VERSION 5.7 ;
  NOWIREEXTENSIONATPIN ON ;
  DIVIDERCHAR "/" ;
  BUSBITCHARS "[]" ;
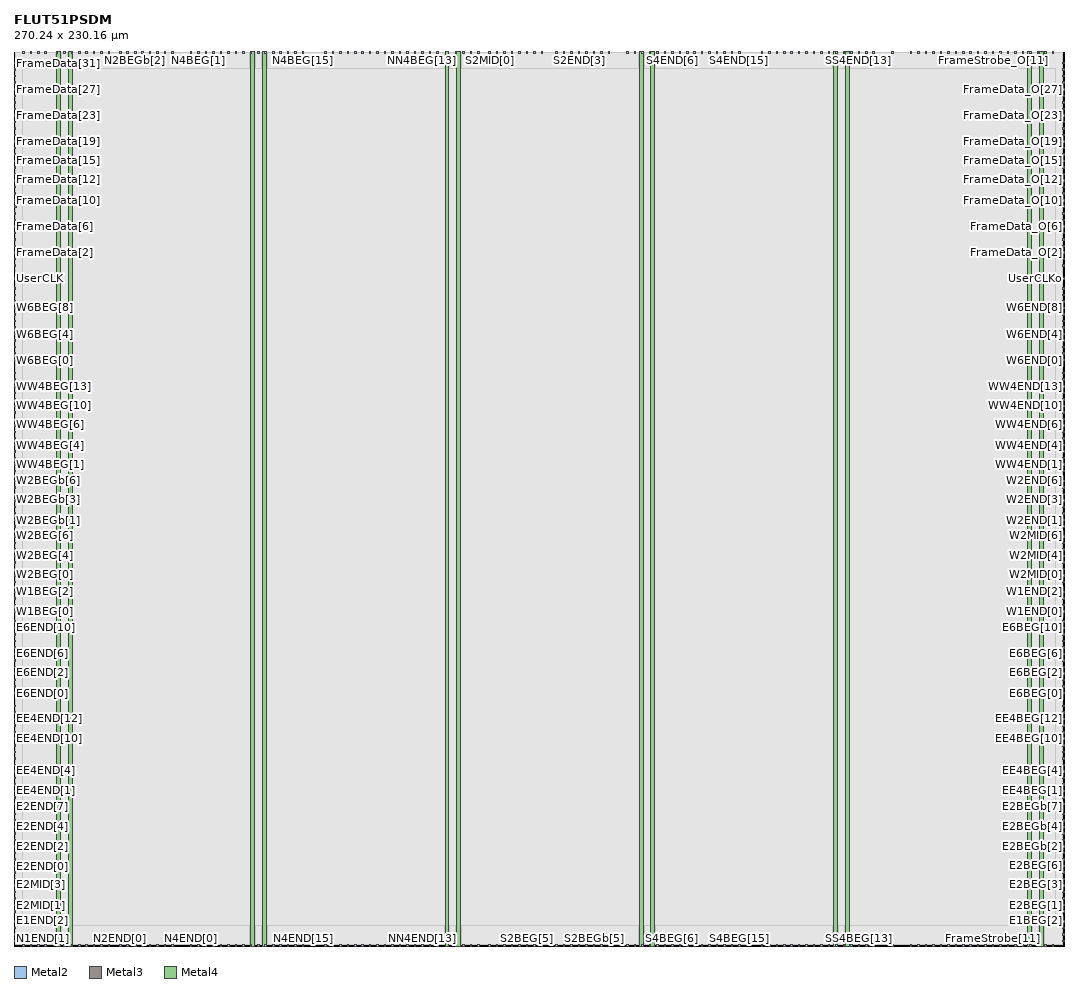
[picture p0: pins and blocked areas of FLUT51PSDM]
MACRO FLUT51PSDM
  CLASS BLOCK ;
  FOREIGN FLUT51PSDM ;
  ORIGIN 0.000 0.000 ;
  SIZE 270.240 BY 230.160 ;
  PIN Ci
    DIRECTION INPUT ;
    USE SIGNAL ;
    ANTENNAGATEAREA 0.241800 ;
    PORT
      LAYER Metal2 ;
        RECT 225.880 0.000 226.280 0.400 ;
    END
  END Ci
  PIN Co
    DIRECTION OUTPUT ;
    USE SIGNAL ;
    ANTENNADIFFAREA 2.647800 ;
    PORT
      LAYER Metal2 ;
        RECT 225.880 229.760 226.280 230.160 ;
    END
  END Co
  PIN E1BEG[0]
    DIRECTION OUTPUT ;
    USE SIGNAL ;
    ANTENNADIFFAREA 2.724000 ;
    PORT
      LAYER Metal3 ;
        RECT 269.840 1.060 270.240 1.460 ;
    END
  END E1BEG[0]
  PIN E1BEG[1]
    DIRECTION OUTPUT ;
    USE SIGNAL ;
    ANTENNADIFFAREA 2.724000 ;
    PORT
      LAYER Metal3 ;
        RECT 269.840 2.740 270.240 3.140 ;
    END
  END E1BEG[1]
  PIN E1BEG[2]
    DIRECTION OUTPUT ;
    USE SIGNAL ;
    ANTENNADIFFAREA 2.724000 ;
    PORT
      LAYER Metal3 ;
        RECT 269.840 4.420 270.240 4.820 ;
    END
  END E1BEG[2]
  PIN E1BEG[3]
    DIRECTION OUTPUT ;
    USE SIGNAL ;
    ANTENNADIFFAREA 2.724000 ;
    PORT
      LAYER Metal3 ;
        RECT 269.840 6.100 270.240 6.500 ;
    END
  END E1BEG[3]
  PIN E1END[0]
    DIRECTION INPUT ;
    USE SIGNAL ;
    ANTENNAGATEAREA 1.705600 ;
    PORT
      LAYER Metal3 ;
        RECT 0.000 1.060 0.400 1.460 ;
    END
  END E1END[0]
  PIN E1END[1]
    DIRECTION INPUT ;
    USE SIGNAL ;
    ANTENNAGATEAREA 2.132000 ;
    PORT
      LAYER Metal3 ;
        RECT 0.000 2.740 0.400 3.140 ;
    END
  END E1END[1]
  PIN E1END[2]
    DIRECTION INPUT ;
    USE SIGNAL ;
    ANTENNAGATEAREA 1.492400 ;
    ANTENNADIFFAREA 42.323399 ;
    PORT
      LAYER Metal3 ;
        RECT 0.000 4.420 0.400 4.820 ;
    END
  END E1END[2]
  PIN E1END[3]
    DIRECTION INPUT ;
    USE SIGNAL ;
    ANTENNAGATEAREA 2.145000 ;
    PORT
      LAYER Metal3 ;
        RECT 0.000 6.100 0.400 6.500 ;
    END
  END E1END[3]
  PIN E2BEG[0]
    DIRECTION OUTPUT ;
    USE SIGNAL ;
    ANTENNADIFFAREA 2.724000 ;
    PORT
      LAYER Metal3 ;
        RECT 269.840 8.620 270.240 9.020 ;
    END
  END E2BEG[0]
  PIN E2BEG[1]
    DIRECTION OUTPUT ;
    USE SIGNAL ;
    ANTENNADIFFAREA 2.724000 ;
    PORT
      LAYER Metal3 ;
        RECT 269.840 10.300 270.240 10.700 ;
    END
  END E2BEG[1]
  PIN E2BEG[2]
    DIRECTION OUTPUT ;
    USE SIGNAL ;
    ANTENNADIFFAREA 2.724000 ;
    PORT
      LAYER Metal3 ;
        RECT 269.840 11.980 270.240 12.380 ;
    END
  END E2BEG[2]
  PIN E2BEG[3]
    DIRECTION OUTPUT ;
    USE SIGNAL ;
    ANTENNADIFFAREA 2.724000 ;
    PORT
      LAYER Metal3 ;
        RECT 269.840 13.660 270.240 14.060 ;
    END
  END E2BEG[3]
  PIN E2BEG[4]
    DIRECTION OUTPUT ;
    USE SIGNAL ;
    ANTENNADIFFAREA 2.724000 ;
    PORT
      LAYER Metal3 ;
        RECT 269.840 15.340 270.240 15.740 ;
    END
  END E2BEG[4]
  PIN E2BEG[5]
    DIRECTION OUTPUT ;
    USE SIGNAL ;
    ANTENNADIFFAREA 2.724000 ;
    PORT
      LAYER Metal3 ;
        RECT 269.840 17.020 270.240 17.420 ;
    END
  END E2BEG[5]
  PIN E2BEG[6]
    DIRECTION OUTPUT ;
    USE SIGNAL ;
    ANTENNADIFFAREA 2.724000 ;
    PORT
      LAYER Metal3 ;
        RECT 269.840 18.700 270.240 19.100 ;
    END
  END E2BEG[6]
  PIN E2BEG[7]
    DIRECTION OUTPUT ;
    USE SIGNAL ;
    ANTENNADIFFAREA 2.724000 ;
    PORT
      LAYER Metal3 ;
        RECT 269.840 20.380 270.240 20.780 ;
    END
  END E2BEG[7]
  PIN E2BEGb[0]
    DIRECTION OUTPUT ;
    USE SIGNAL ;
    ANTENNADIFFAREA 2.724000 ;
    PORT
      LAYER Metal3 ;
        RECT 269.840 22.060 270.240 22.460 ;
    END
  END E2BEGb[0]
  PIN E2BEGb[1]
    DIRECTION OUTPUT ;
    USE SIGNAL ;
    ANTENNADIFFAREA 2.724000 ;
    PORT
      LAYER Metal3 ;
        RECT 269.840 23.740 270.240 24.140 ;
    END
  END E2BEGb[1]
  PIN E2BEGb[2]
    DIRECTION OUTPUT ;
    USE SIGNAL ;
    ANTENNADIFFAREA 2.724000 ;
    PORT
      LAYER Metal3 ;
        RECT 269.840 25.420 270.240 25.820 ;
    END
  END E2BEGb[2]
  PIN E2BEGb[3]
    DIRECTION OUTPUT ;
    USE SIGNAL ;
    ANTENNADIFFAREA 2.724000 ;
    PORT
      LAYER Metal3 ;
        RECT 269.840 27.100 270.240 27.500 ;
    END
  END E2BEGb[3]
  PIN E2BEGb[4]
    DIRECTION OUTPUT ;
    USE SIGNAL ;
    ANTENNADIFFAREA 2.724000 ;
    PORT
      LAYER Metal3 ;
        RECT 269.840 28.780 270.240 29.180 ;
    END
  END E2BEGb[4]
  PIN E2BEGb[5]
    DIRECTION OUTPUT ;
    USE SIGNAL ;
    ANTENNADIFFAREA 2.724000 ;
    PORT
      LAYER Metal3 ;
        RECT 269.840 30.460 270.240 30.860 ;
    END
  END E2BEGb[5]
  PIN E2BEGb[6]
    DIRECTION OUTPUT ;
    USE SIGNAL ;
    ANTENNADIFFAREA 2.724000 ;
    PORT
      LAYER Metal3 ;
        RECT 269.840 32.140 270.240 32.540 ;
    END
  END E2BEGb[6]
  PIN E2BEGb[7]
    DIRECTION OUTPUT ;
    USE SIGNAL ;
    ANTENNADIFFAREA 2.724000 ;
    PORT
      LAYER Metal3 ;
        RECT 269.840 33.820 270.240 34.220 ;
    END
  END E2BEGb[7]
  PIN E2END[0]
    DIRECTION INPUT ;
    USE SIGNAL ;
    ANTENNAGATEAREA 0.852800 ;
    ANTENNADIFFAREA 8.061600 ;
    PORT
      LAYER Metal3 ;
        RECT 0.000 22.060 0.400 22.460 ;
    END
  END E2END[0]
  PIN E2END[1]
    DIRECTION INPUT ;
    USE SIGNAL ;
    ANTENNAGATEAREA 1.279200 ;
    PORT
      LAYER Metal3 ;
        RECT 0.000 23.740 0.400 24.140 ;
    END
  END E2END[1]
  PIN E2END[2]
    DIRECTION INPUT ;
    USE SIGNAL ;
    ANTENNAGATEAREA 1.279200 ;
    PORT
      LAYER Metal3 ;
        RECT 0.000 25.420 0.400 25.820 ;
    END
  END E2END[2]
  PIN E2END[3]
    DIRECTION INPUT ;
    USE SIGNAL ;
    ANTENNAGATEAREA 1.492400 ;
    PORT
      LAYER Metal3 ;
        RECT 0.000 27.100 0.400 27.500 ;
    END
  END E2END[3]
  PIN E2END[4]
    DIRECTION INPUT ;
    USE SIGNAL ;
    ANTENNAGATEAREA 1.705600 ;
    PORT
      LAYER Metal3 ;
        RECT 0.000 28.780 0.400 29.180 ;
    END
  END E2END[4]
  PIN E2END[5]
    DIRECTION INPUT ;
    USE SIGNAL ;
    ANTENNAGATEAREA 1.492400 ;
    PORT
      LAYER Metal3 ;
        RECT 0.000 30.460 0.400 30.860 ;
    END
  END E2END[5]
  PIN E2END[6]
    DIRECTION INPUT ;
    USE SIGNAL ;
    ANTENNAGATEAREA 1.492400 ;
    PORT
      LAYER Metal3 ;
        RECT 0.000 32.140 0.400 32.540 ;
    END
  END E2END[6]
  PIN E2END[7]
    DIRECTION INPUT ;
    USE SIGNAL ;
    ANTENNAGATEAREA 1.066000 ;
    PORT
      LAYER Metal3 ;
        RECT 0.000 33.820 0.400 34.220 ;
    END
  END E2END[7]
  PIN E2MID[0]
    DIRECTION INPUT ;
    USE SIGNAL ;
    ANTENNAGATEAREA 2.099500 ;
    PORT
      LAYER Metal3 ;
        RECT 0.000 8.620 0.400 9.020 ;
    END
  END E2MID[0]
  PIN E2MID[1]
    DIRECTION INPUT ;
    USE SIGNAL ;
    ANTENNAGATEAREA 1.459900 ;
    PORT
      LAYER Metal3 ;
        RECT 0.000 10.300 0.400 10.700 ;
    END
  END E2MID[1]
  PIN E2MID[2]
    DIRECTION INPUT ;
    USE SIGNAL ;
    ANTENNAGATEAREA 1.673100 ;
    PORT
      LAYER Metal3 ;
        RECT 0.000 11.980 0.400 12.380 ;
    END
  END E2MID[2]
  PIN E2MID[3]
    DIRECTION INPUT ;
    USE SIGNAL ;
    ANTENNAGATEAREA 2.312700 ;
    PORT
      LAYER Metal3 ;
        RECT 0.000 13.660 0.400 14.060 ;
    END
  END E2MID[3]
  PIN E2MID[4]
    DIRECTION INPUT ;
    USE SIGNAL ;
    ANTENNAGATEAREA 1.673100 ;
    PORT
      LAYER Metal3 ;
        RECT 0.000 15.340 0.400 15.740 ;
    END
  END E2MID[4]
  PIN E2MID[5]
    DIRECTION INPUT ;
    USE SIGNAL ;
    ANTENNAGATEAREA 1.459900 ;
    PORT
      LAYER Metal3 ;
        RECT 0.000 17.020 0.400 17.420 ;
    END
  END E2MID[5]
  PIN E2MID[6]
    DIRECTION INPUT ;
    USE SIGNAL ;
    ANTENNAGATEAREA 1.699100 ;
    PORT
      LAYER Metal3 ;
        RECT 0.000 18.700 0.400 19.100 ;
    END
  END E2MID[6]
  PIN E2MID[7]
    DIRECTION INPUT ;
    USE SIGNAL ;
    ANTENNAGATEAREA 1.459900 ;
    PORT
      LAYER Metal3 ;
        RECT 0.000 20.380 0.400 20.780 ;
    END
  END E2MID[7]
  PIN E6BEG[0]
    DIRECTION OUTPUT ;
    USE SIGNAL ;
    ANTENNADIFFAREA 2.724000 ;
    PORT
      LAYER Metal3 ;
        RECT 269.840 64.900 270.240 65.300 ;
    END
  END E6BEG[0]
  PIN E6BEG[10]
    DIRECTION OUTPUT ;
    USE SIGNAL ;
    ANTENNADIFFAREA 2.724000 ;
    PORT
      LAYER Metal3 ;
        RECT 269.840 81.700 270.240 82.100 ;
    END
  END E6BEG[10]
  PIN E6BEG[11]
    DIRECTION OUTPUT ;
    USE SIGNAL ;
    ANTENNADIFFAREA 2.724000 ;
    PORT
      LAYER Metal3 ;
        RECT 269.840 83.380 270.240 83.780 ;
    END
  END E6BEG[11]
  PIN E6BEG[1]
    DIRECTION OUTPUT ;
    USE SIGNAL ;
    ANTENNADIFFAREA 2.724000 ;
    PORT
      LAYER Metal3 ;
        RECT 269.840 66.580 270.240 66.980 ;
    END
  END E6BEG[1]
  PIN E6BEG[2]
    DIRECTION OUTPUT ;
    USE SIGNAL ;
    ANTENNADIFFAREA 2.724000 ;
    PORT
      LAYER Metal3 ;
        RECT 269.840 68.260 270.240 68.660 ;
    END
  END E6BEG[2]
  PIN E6BEG[3]
    DIRECTION OUTPUT ;
    USE SIGNAL ;
    ANTENNADIFFAREA 2.724000 ;
    PORT
      LAYER Metal3 ;
        RECT 269.840 69.940 270.240 70.340 ;
    END
  END E6BEG[3]
  PIN E6BEG[4]
    DIRECTION OUTPUT ;
    USE SIGNAL ;
    ANTENNADIFFAREA 2.724000 ;
    PORT
      LAYER Metal3 ;
        RECT 269.840 71.620 270.240 72.020 ;
    END
  END E6BEG[4]
  PIN E6BEG[5]
    DIRECTION OUTPUT ;
    USE SIGNAL ;
    ANTENNADIFFAREA 2.724000 ;
    PORT
      LAYER Metal3 ;
        RECT 269.840 73.300 270.240 73.700 ;
    END
  END E6BEG[5]
  PIN E6BEG[6]
    DIRECTION OUTPUT ;
    USE SIGNAL ;
    ANTENNADIFFAREA 2.724000 ;
    PORT
      LAYER Metal3 ;
        RECT 269.840 74.980 270.240 75.380 ;
    END
  END E6BEG[6]
  PIN E6BEG[7]
    DIRECTION OUTPUT ;
    USE SIGNAL ;
    ANTENNADIFFAREA 2.724000 ;
    PORT
      LAYER Metal3 ;
        RECT 269.840 76.660 270.240 77.060 ;
    END
  END E6BEG[7]
  PIN E6BEG[8]
    DIRECTION OUTPUT ;
    USE SIGNAL ;
    ANTENNADIFFAREA 2.724000 ;
    PORT
      LAYER Metal3 ;
        RECT 269.840 78.340 270.240 78.740 ;
    END
  END E6BEG[8]
  PIN E6BEG[9]
    DIRECTION OUTPUT ;
    USE SIGNAL ;
    ANTENNADIFFAREA 2.724000 ;
    PORT
      LAYER Metal3 ;
        RECT 269.840 80.020 270.240 80.420 ;
    END
  END E6BEG[9]
  PIN E6END[0]
    DIRECTION INPUT ;
    USE SIGNAL ;
    ANTENNAGATEAREA 1.918800 ;
    PORT
      LAYER Metal3 ;
        RECT 0.000 64.900 0.400 65.300 ;
    END
  END E6END[0]
  PIN E6END[10]
    DIRECTION INPUT ;
    USE SIGNAL ;
    ANTENNAGATEAREA 0.180700 ;
    PORT
      LAYER Metal3 ;
        RECT 0.000 81.700 0.400 82.100 ;
    END
  END E6END[10]
  PIN E6END[11]
    DIRECTION INPUT ;
    USE SIGNAL ;
    ANTENNAGATEAREA 0.180700 ;
    PORT
      LAYER Metal3 ;
        RECT 0.000 83.380 0.400 83.780 ;
    END
  END E6END[11]
  PIN E6END[1]
    DIRECTION INPUT ;
    USE SIGNAL ;
    ANTENNAGATEAREA 2.345200 ;
    PORT
      LAYER Metal3 ;
        RECT 0.000 66.580 0.400 66.980 ;
    END
  END E6END[1]
  PIN E6END[2]
    DIRECTION INPUT ;
    USE SIGNAL ;
    ANTENNAGATEAREA 0.180700 ;
    PORT
      LAYER Metal3 ;
        RECT 0.000 68.260 0.400 68.660 ;
    END
  END E6END[2]
  PIN E6END[3]
    DIRECTION INPUT ;
    USE SIGNAL ;
    ANTENNAGATEAREA 0.180700 ;
    PORT
      LAYER Metal3 ;
        RECT 0.000 69.940 0.400 70.340 ;
    END
  END E6END[3]
  PIN E6END[4]
    DIRECTION INPUT ;
    USE SIGNAL ;
    ANTENNAGATEAREA 0.180700 ;
    PORT
      LAYER Metal3 ;
        RECT 0.000 71.620 0.400 72.020 ;
    END
  END E6END[4]
  PIN E6END[5]
    DIRECTION INPUT ;
    USE SIGNAL ;
    ANTENNAGATEAREA 0.180700 ;
    PORT
      LAYER Metal3 ;
        RECT 0.000 73.300 0.400 73.700 ;
    END
  END E6END[5]
  PIN E6END[6]
    DIRECTION INPUT ;
    USE SIGNAL ;
    ANTENNAGATEAREA 0.180700 ;
    PORT
      LAYER Metal3 ;
        RECT 0.000 74.980 0.400 75.380 ;
    END
  END E6END[6]
  PIN E6END[7]
    DIRECTION INPUT ;
    USE SIGNAL ;
    ANTENNAGATEAREA 0.180700 ;
    PORT
      LAYER Metal3 ;
        RECT 0.000 76.660 0.400 77.060 ;
    END
  END E6END[7]
  PIN E6END[8]
    DIRECTION INPUT ;
    USE SIGNAL ;
    ANTENNAGATEAREA 0.180700 ;
    PORT
      LAYER Metal3 ;
        RECT 0.000 78.340 0.400 78.740 ;
    END
  END E6END[8]
  PIN E6END[9]
    DIRECTION INPUT ;
    USE SIGNAL ;
    ANTENNAGATEAREA 0.180700 ;
    PORT
      LAYER Metal3 ;
        RECT 0.000 80.020 0.400 80.420 ;
    END
  END E6END[9]
  PIN EE4BEG[0]
    DIRECTION OUTPUT ;
    USE SIGNAL ;
    ANTENNADIFFAREA 2.724000 ;
    PORT
      LAYER Metal3 ;
        RECT 269.840 36.340 270.240 36.740 ;
    END
  END EE4BEG[0]
  PIN EE4BEG[10]
    DIRECTION OUTPUT ;
    USE SIGNAL ;
    ANTENNADIFFAREA 2.724000 ;
    PORT
      LAYER Metal3 ;
        RECT 269.840 53.140 270.240 53.540 ;
    END
  END EE4BEG[10]
  PIN EE4BEG[11]
    DIRECTION OUTPUT ;
    USE SIGNAL ;
    ANTENNADIFFAREA 2.724000 ;
    PORT
      LAYER Metal3 ;
        RECT 269.840 54.820 270.240 55.220 ;
    END
  END EE4BEG[11]
  PIN EE4BEG[12]
    DIRECTION OUTPUT ;
    USE SIGNAL ;
    ANTENNADIFFAREA 2.724000 ;
    PORT
      LAYER Metal3 ;
        RECT 269.840 56.500 270.240 56.900 ;
    END
  END EE4BEG[12]
  PIN EE4BEG[13]
    DIRECTION OUTPUT ;
    USE SIGNAL ;
    ANTENNADIFFAREA 2.724000 ;
    PORT
      LAYER Metal3 ;
        RECT 269.840 58.180 270.240 58.580 ;
    END
  END EE4BEG[13]
  PIN EE4BEG[14]
    DIRECTION OUTPUT ;
    USE SIGNAL ;
    ANTENNADIFFAREA 2.724000 ;
    PORT
      LAYER Metal3 ;
        RECT 269.840 59.860 270.240 60.260 ;
    END
  END EE4BEG[14]
  PIN EE4BEG[15]
    DIRECTION OUTPUT ;
    USE SIGNAL ;
    ANTENNADIFFAREA 2.724000 ;
    PORT
      LAYER Metal3 ;
        RECT 269.840 61.540 270.240 61.940 ;
    END
  END EE4BEG[15]
  PIN EE4BEG[1]
    DIRECTION OUTPUT ;
    USE SIGNAL ;
    ANTENNADIFFAREA 2.724000 ;
    PORT
      LAYER Metal3 ;
        RECT 269.840 38.020 270.240 38.420 ;
    END
  END EE4BEG[1]
  PIN EE4BEG[2]
    DIRECTION OUTPUT ;
    USE SIGNAL ;
    ANTENNADIFFAREA 2.724000 ;
    PORT
      LAYER Metal3 ;
        RECT 269.840 39.700 270.240 40.100 ;
    END
  END EE4BEG[2]
  PIN EE4BEG[3]
    DIRECTION OUTPUT ;
    USE SIGNAL ;
    ANTENNADIFFAREA 2.724000 ;
    PORT
      LAYER Metal3 ;
        RECT 269.840 41.380 270.240 41.780 ;
    END
  END EE4BEG[3]
  PIN EE4BEG[4]
    DIRECTION OUTPUT ;
    USE SIGNAL ;
    ANTENNADIFFAREA 2.724000 ;
    PORT
      LAYER Metal3 ;
        RECT 269.840 43.060 270.240 43.460 ;
    END
  END EE4BEG[4]
  PIN EE4BEG[5]
    DIRECTION OUTPUT ;
    USE SIGNAL ;
    ANTENNADIFFAREA 2.724000 ;
    PORT
      LAYER Metal3 ;
        RECT 269.840 44.740 270.240 45.140 ;
    END
  END EE4BEG[5]
  PIN EE4BEG[6]
    DIRECTION OUTPUT ;
    USE SIGNAL ;
    ANTENNADIFFAREA 2.724000 ;
    PORT
      LAYER Metal3 ;
        RECT 269.840 46.420 270.240 46.820 ;
    END
  END EE4BEG[6]
  PIN EE4BEG[7]
    DIRECTION OUTPUT ;
    USE SIGNAL ;
    ANTENNADIFFAREA 2.724000 ;
    PORT
      LAYER Metal3 ;
        RECT 269.840 48.100 270.240 48.500 ;
    END
  END EE4BEG[7]
  PIN EE4BEG[8]
    DIRECTION OUTPUT ;
    USE SIGNAL ;
    ANTENNADIFFAREA 2.724000 ;
    PORT
      LAYER Metal3 ;
        RECT 269.840 49.780 270.240 50.180 ;
    END
  END EE4BEG[8]
  PIN EE4BEG[9]
    DIRECTION OUTPUT ;
    USE SIGNAL ;
    ANTENNADIFFAREA 2.724000 ;
    PORT
      LAYER Metal3 ;
        RECT 269.840 51.460 270.240 51.860 ;
    END
  END EE4BEG[9]
  PIN EE4END[0]
    DIRECTION INPUT ;
    USE SIGNAL ;
    ANTENNAGATEAREA 1.918800 ;
    PORT
      LAYER Metal3 ;
        RECT 0.000 36.340 0.400 36.740 ;
    END
  END EE4END[0]
  PIN EE4END[10]
    DIRECTION INPUT ;
    USE SIGNAL ;
    ANTENNAGATEAREA 0.180700 ;
    PORT
      LAYER Metal3 ;
        RECT 0.000 53.140 0.400 53.540 ;
    END
  END EE4END[10]
  PIN EE4END[11]
    DIRECTION INPUT ;
    USE SIGNAL ;
    ANTENNAGATEAREA 0.180700 ;
    PORT
      LAYER Metal3 ;
        RECT 0.000 54.820 0.400 55.220 ;
    END
  END EE4END[11]
  PIN EE4END[12]
    DIRECTION INPUT ;
    USE SIGNAL ;
    ANTENNAGATEAREA 0.180700 ;
    PORT
      LAYER Metal3 ;
        RECT 0.000 56.500 0.400 56.900 ;
    END
  END EE4END[12]
  PIN EE4END[13]
    DIRECTION INPUT ;
    USE SIGNAL ;
    ANTENNAGATEAREA 0.180700 ;
    PORT
      LAYER Metal3 ;
        RECT 0.000 58.180 0.400 58.580 ;
    END
  END EE4END[13]
  PIN EE4END[14]
    DIRECTION INPUT ;
    USE SIGNAL ;
    ANTENNAGATEAREA 0.180700 ;
    PORT
      LAYER Metal3 ;
        RECT 0.000 59.860 0.400 60.260 ;
    END
  END EE4END[14]
  PIN EE4END[15]
    DIRECTION INPUT ;
    USE SIGNAL ;
    ANTENNAGATEAREA 0.180700 ;
    PORT
      LAYER Metal3 ;
        RECT 0.000 61.540 0.400 61.940 ;
    END
  END EE4END[15]
  PIN EE4END[1]
    DIRECTION INPUT ;
    USE SIGNAL ;
    ANTENNAGATEAREA 1.492400 ;
    PORT
      LAYER Metal3 ;
        RECT 0.000 38.020 0.400 38.420 ;
    END
  END EE4END[1]
  PIN EE4END[2]
    DIRECTION INPUT ;
    USE SIGNAL ;
    ANTENNAGATEAREA 1.705600 ;
    PORT
      LAYER Metal3 ;
        RECT 0.000 39.700 0.400 40.100 ;
    END
  END EE4END[2]
  PIN EE4END[3]
    DIRECTION INPUT ;
    USE SIGNAL ;
    ANTENNAGATEAREA 1.492400 ;
    PORT
      LAYER Metal3 ;
        RECT 0.000 41.380 0.400 41.780 ;
    END
  END EE4END[3]
  PIN EE4END[4]
    DIRECTION INPUT ;
    USE SIGNAL ;
    ANTENNAGATEAREA 0.180700 ;
    PORT
      LAYER Metal3 ;
        RECT 0.000 43.060 0.400 43.460 ;
    END
  END EE4END[4]
  PIN EE4END[5]
    DIRECTION INPUT ;
    USE SIGNAL ;
    ANTENNAGATEAREA 0.180700 ;
    PORT
      LAYER Metal3 ;
        RECT 0.000 44.740 0.400 45.140 ;
    END
  END EE4END[5]
  PIN EE4END[6]
    DIRECTION INPUT ;
    USE SIGNAL ;
    ANTENNAGATEAREA 0.180700 ;
    PORT
      LAYER Metal3 ;
        RECT 0.000 46.420 0.400 46.820 ;
    END
  END EE4END[6]
  PIN EE4END[7]
    DIRECTION INPUT ;
    USE SIGNAL ;
    ANTENNAGATEAREA 0.180700 ;
    PORT
      LAYER Metal3 ;
        RECT 0.000 48.100 0.400 48.500 ;
    END
  END EE4END[7]
  PIN EE4END[8]
    DIRECTION INPUT ;
    USE SIGNAL ;
    ANTENNAGATEAREA 0.180700 ;
    PORT
      LAYER Metal3 ;
        RECT 0.000 49.780 0.400 50.180 ;
    END
  END EE4END[8]
  PIN EE4END[9]
    DIRECTION INPUT ;
    USE SIGNAL ;
    ANTENNAGATEAREA 0.180700 ;
    PORT
      LAYER Metal3 ;
        RECT 0.000 51.460 0.400 51.860 ;
    END
  END EE4END[9]
  PIN FrameData[0]
    DIRECTION INPUT ;
    USE SIGNAL ;
    ANTENNAGATEAREA 6.143800 ;
    PORT
      LAYER Metal3 ;
        RECT 0.000 174.940 0.400 175.340 ;
    END
  END FrameData[0]
  PIN FrameData[10]
    DIRECTION INPUT ;
    USE SIGNAL ;
    ANTENNAGATEAREA 6.324500 ;
    PORT
      LAYER Metal3 ;
        RECT 0.000 191.740 0.400 192.140 ;
    END
  END FrameData[10]
  PIN FrameData[11]
    DIRECTION INPUT ;
    USE SIGNAL ;
    ANTENNAGATEAREA 6.324500 ;
    PORT
      LAYER Metal3 ;
        RECT 0.000 193.420 0.400 193.820 ;
    END
  END FrameData[11]
  PIN FrameData[12]
    DIRECTION INPUT ;
    USE SIGNAL ;
    ANTENNAGATEAREA 6.324500 ;
    PORT
      LAYER Metal3 ;
        RECT 0.000 195.100 0.400 195.500 ;
    END
  END FrameData[12]
  PIN FrameData[13]
    DIRECTION INPUT ;
    USE SIGNAL ;
    ANTENNAGATEAREA 6.324500 ;
    PORT
      LAYER Metal3 ;
        RECT 0.000 196.780 0.400 197.180 ;
    END
  END FrameData[13]
  PIN FrameData[14]
    DIRECTION INPUT ;
    USE SIGNAL ;
    ANTENNAGATEAREA 6.324500 ;
    PORT
      LAYER Metal3 ;
        RECT 0.000 198.460 0.400 198.860 ;
    END
  END FrameData[14]
  PIN FrameData[15]
    DIRECTION INPUT ;
    USE SIGNAL ;
    ANTENNAGATEAREA 6.324500 ;
    PORT
      LAYER Metal3 ;
        RECT 0.000 200.140 0.400 200.540 ;
    END
  END FrameData[15]
  PIN FrameData[16]
    DIRECTION INPUT ;
    USE SIGNAL ;
    ANTENNAGATEAREA 6.324500 ;
    PORT
      LAYER Metal3 ;
        RECT 0.000 201.820 0.400 202.220 ;
    END
  END FrameData[16]
  PIN FrameData[17]
    DIRECTION INPUT ;
    USE SIGNAL ;
    ANTENNAGATEAREA 6.324500 ;
    PORT
      LAYER Metal3 ;
        RECT 0.000 203.500 0.400 203.900 ;
    END
  END FrameData[17]
  PIN FrameData[18]
    DIRECTION INPUT ;
    USE SIGNAL ;
    ANTENNAGATEAREA 6.324500 ;
    PORT
      LAYER Metal3 ;
        RECT 0.000 205.180 0.400 205.580 ;
    END
  END FrameData[18]
  PIN FrameData[19]
    DIRECTION INPUT ;
    USE SIGNAL ;
    ANTENNAGATEAREA 6.324500 ;
    PORT
      LAYER Metal3 ;
        RECT 0.000 206.860 0.400 207.260 ;
    END
  END FrameData[19]
  PIN FrameData[1]
    DIRECTION INPUT ;
    USE SIGNAL ;
    ANTENNAGATEAREA 6.143800 ;
    PORT
      LAYER Metal3 ;
        RECT 0.000 176.620 0.400 177.020 ;
    END
  END FrameData[1]
  PIN FrameData[20]
    DIRECTION INPUT ;
    USE SIGNAL ;
    ANTENNAGATEAREA 6.324500 ;
    PORT
      LAYER Metal3 ;
        RECT 0.000 208.540 0.400 208.940 ;
    END
  END FrameData[20]
  PIN FrameData[21]
    DIRECTION INPUT ;
    USE SIGNAL ;
    ANTENNAGATEAREA 6.324500 ;
    PORT
      LAYER Metal3 ;
        RECT 0.000 210.220 0.400 210.620 ;
    END
  END FrameData[21]
  PIN FrameData[22]
    DIRECTION INPUT ;
    USE SIGNAL ;
    ANTENNAGATEAREA 6.324500 ;
    PORT
      LAYER Metal3 ;
        RECT 0.000 211.900 0.400 212.300 ;
    END
  END FrameData[22]
  PIN FrameData[23]
    DIRECTION INPUT ;
    USE SIGNAL ;
    ANTENNAGATEAREA 6.324500 ;
    PORT
      LAYER Metal3 ;
        RECT 0.000 213.580 0.400 213.980 ;
    END
  END FrameData[23]
  PIN FrameData[24]
    DIRECTION INPUT ;
    USE SIGNAL ;
    ANTENNAGATEAREA 6.324500 ;
    PORT
      LAYER Metal3 ;
        RECT 0.000 215.260 0.400 215.660 ;
    END
  END FrameData[24]
  PIN FrameData[25]
    DIRECTION INPUT ;
    USE SIGNAL ;
    ANTENNAGATEAREA 6.324500 ;
    PORT
      LAYER Metal3 ;
        RECT 0.000 216.940 0.400 217.340 ;
    END
  END FrameData[25]
  PIN FrameData[26]
    DIRECTION INPUT ;
    USE SIGNAL ;
    ANTENNAGATEAREA 6.324500 ;
    PORT
      LAYER Metal3 ;
        RECT 0.000 218.620 0.400 219.020 ;
    END
  END FrameData[26]
  PIN FrameData[27]
    DIRECTION INPUT ;
    USE SIGNAL ;
    ANTENNAGATEAREA 6.324500 ;
    PORT
      LAYER Metal3 ;
        RECT 0.000 220.300 0.400 220.700 ;
    END
  END FrameData[27]
  PIN FrameData[28]
    DIRECTION INPUT ;
    USE SIGNAL ;
    ANTENNAGATEAREA 6.324500 ;
    PORT
      LAYER Metal3 ;
        RECT 0.000 221.980 0.400 222.380 ;
    END
  END FrameData[28]
  PIN FrameData[29]
    DIRECTION INPUT ;
    USE SIGNAL ;
    ANTENNAGATEAREA 6.324500 ;
    PORT
      LAYER Metal3 ;
        RECT 0.000 223.660 0.400 224.060 ;
    END
  END FrameData[29]
  PIN FrameData[2]
    DIRECTION INPUT ;
    USE SIGNAL ;
    ANTENNAGATEAREA 6.143800 ;
    PORT
      LAYER Metal3 ;
        RECT 0.000 178.300 0.400 178.700 ;
    END
  END FrameData[2]
  PIN FrameData[30]
    DIRECTION INPUT ;
    USE SIGNAL ;
    ANTENNAGATEAREA 6.324500 ;
    PORT
      LAYER Metal3 ;
        RECT 0.000 225.340 0.400 225.740 ;
    END
  END FrameData[30]
  PIN FrameData[31]
    DIRECTION INPUT ;
    USE SIGNAL ;
    ANTENNAGATEAREA 6.324500 ;
    PORT
      LAYER Metal3 ;
        RECT 0.000 227.020 0.400 227.420 ;
    END
  END FrameData[31]
  PIN FrameData[3]
    DIRECTION INPUT ;
    USE SIGNAL ;
    ANTENNAGATEAREA 6.143800 ;
    PORT
      LAYER Metal3 ;
        RECT 0.000 179.980 0.400 180.380 ;
    END
  END FrameData[3]
  PIN FrameData[4]
    DIRECTION INPUT ;
    USE SIGNAL ;
    ANTENNAGATEAREA 6.143800 ;
    PORT
      LAYER Metal3 ;
        RECT 0.000 181.660 0.400 182.060 ;
    END
  END FrameData[4]
  PIN FrameData[5]
    DIRECTION INPUT ;
    USE SIGNAL ;
    ANTENNAGATEAREA 6.143800 ;
    PORT
      LAYER Metal3 ;
        RECT 0.000 183.340 0.400 183.740 ;
    END
  END FrameData[5]
  PIN FrameData[6]
    DIRECTION INPUT ;
    USE SIGNAL ;
    ANTENNAGATEAREA 6.143800 ;
    PORT
      LAYER Metal3 ;
        RECT 0.000 185.020 0.400 185.420 ;
    END
  END FrameData[6]
  PIN FrameData[7]
    DIRECTION INPUT ;
    USE SIGNAL ;
    ANTENNAGATEAREA 6.143800 ;
    PORT
      LAYER Metal3 ;
        RECT 0.000 186.700 0.400 187.100 ;
    END
  END FrameData[7]
  PIN FrameData[8]
    DIRECTION INPUT ;
    USE SIGNAL ;
    ANTENNAGATEAREA 6.324500 ;
    PORT
      LAYER Metal3 ;
        RECT 0.000 188.380 0.400 188.780 ;
    END
  END FrameData[8]
  PIN FrameData[9]
    DIRECTION INPUT ;
    USE SIGNAL ;
    ANTENNAGATEAREA 6.324500 ;
    PORT
      LAYER Metal3 ;
        RECT 0.000 190.060 0.580 190.460 ;
    END
  END FrameData[9]
  PIN FrameData_O[0]
    DIRECTION OUTPUT ;
    USE SIGNAL ;
    ANTENNADIFFAREA 2.724000 ;
    PORT
      LAYER Metal3 ;
        RECT 269.840 174.940 270.240 175.340 ;
    END
  END FrameData_O[0]
  PIN FrameData_O[10]
    DIRECTION OUTPUT ;
    USE SIGNAL ;
    ANTENNADIFFAREA 2.724000 ;
    PORT
      LAYER Metal3 ;
        RECT 269.840 191.740 270.240 192.140 ;
    END
  END FrameData_O[10]
  PIN FrameData_O[11]
    DIRECTION OUTPUT ;
    USE SIGNAL ;
    ANTENNADIFFAREA 2.724000 ;
    PORT
      LAYER Metal3 ;
        RECT 269.840 193.420 270.240 193.820 ;
    END
  END FrameData_O[11]
  PIN FrameData_O[12]
    DIRECTION OUTPUT ;
    USE SIGNAL ;
    ANTENNADIFFAREA 2.724000 ;
    PORT
      LAYER Metal3 ;
        RECT 269.840 195.100 270.240 195.500 ;
    END
  END FrameData_O[12]
  PIN FrameData_O[13]
    DIRECTION OUTPUT ;
    USE SIGNAL ;
    ANTENNADIFFAREA 2.724000 ;
    PORT
      LAYER Metal3 ;
        RECT 269.840 196.780 270.240 197.180 ;
    END
  END FrameData_O[13]
  PIN FrameData_O[14]
    DIRECTION OUTPUT ;
    USE SIGNAL ;
    ANTENNADIFFAREA 2.724000 ;
    PORT
      LAYER Metal3 ;
        RECT 269.840 198.460 270.240 198.860 ;
    END
  END FrameData_O[14]
  PIN FrameData_O[15]
    DIRECTION OUTPUT ;
    USE SIGNAL ;
    ANTENNADIFFAREA 2.724000 ;
    PORT
      LAYER Metal3 ;
        RECT 269.840 200.140 270.240 200.540 ;
    END
  END FrameData_O[15]
  PIN FrameData_O[16]
    DIRECTION OUTPUT ;
    USE SIGNAL ;
    ANTENNADIFFAREA 2.724000 ;
    PORT
      LAYER Metal3 ;
        RECT 269.840 201.820 270.240 202.220 ;
    END
  END FrameData_O[16]
  PIN FrameData_O[17]
    DIRECTION OUTPUT ;
    USE SIGNAL ;
    ANTENNADIFFAREA 2.724000 ;
    PORT
      LAYER Metal3 ;
        RECT 269.840 203.500 270.240 203.900 ;
    END
  END FrameData_O[17]
  PIN FrameData_O[18]
    DIRECTION OUTPUT ;
    USE SIGNAL ;
    ANTENNADIFFAREA 2.724000 ;
    PORT
      LAYER Metal3 ;
        RECT 269.840 205.180 270.240 205.580 ;
    END
  END FrameData_O[18]
  PIN FrameData_O[19]
    DIRECTION OUTPUT ;
    USE SIGNAL ;
    ANTENNADIFFAREA 2.724000 ;
    PORT
      LAYER Metal3 ;
        RECT 269.840 206.860 270.240 207.260 ;
    END
  END FrameData_O[19]
  PIN FrameData_O[1]
    DIRECTION OUTPUT ;
    USE SIGNAL ;
    ANTENNADIFFAREA 2.724000 ;
    PORT
      LAYER Metal3 ;
        RECT 269.840 176.620 270.240 177.020 ;
    END
  END FrameData_O[1]
  PIN FrameData_O[20]
    DIRECTION OUTPUT ;
    USE SIGNAL ;
    ANTENNADIFFAREA 2.724000 ;
    PORT
      LAYER Metal3 ;
        RECT 269.840 208.540 270.240 208.940 ;
    END
  END FrameData_O[20]
  PIN FrameData_O[21]
    DIRECTION OUTPUT ;
    USE SIGNAL ;
    ANTENNADIFFAREA 2.724000 ;
    PORT
      LAYER Metal3 ;
        RECT 269.840 210.220 270.240 210.620 ;
    END
  END FrameData_O[21]
  PIN FrameData_O[22]
    DIRECTION OUTPUT ;
    USE SIGNAL ;
    ANTENNADIFFAREA 2.724000 ;
    PORT
      LAYER Metal3 ;
        RECT 269.840 211.900 270.240 212.300 ;
    END
  END FrameData_O[22]
  PIN FrameData_O[23]
    DIRECTION OUTPUT ;
    USE SIGNAL ;
    ANTENNADIFFAREA 2.724000 ;
    PORT
      LAYER Metal3 ;
        RECT 269.840 213.580 270.240 213.980 ;
    END
  END FrameData_O[23]
  PIN FrameData_O[24]
    DIRECTION OUTPUT ;
    USE SIGNAL ;
    ANTENNADIFFAREA 2.724000 ;
    PORT
      LAYER Metal3 ;
        RECT 269.840 215.260 270.240 215.660 ;
    END
  END FrameData_O[24]
  PIN FrameData_O[25]
    DIRECTION OUTPUT ;
    USE SIGNAL ;
    ANTENNADIFFAREA 2.724000 ;
    PORT
      LAYER Metal3 ;
        RECT 269.840 216.940 270.240 217.340 ;
    END
  END FrameData_O[25]
  PIN FrameData_O[26]
    DIRECTION OUTPUT ;
    USE SIGNAL ;
    ANTENNADIFFAREA 2.724000 ;
    PORT
      LAYER Metal3 ;
        RECT 269.840 218.620 270.240 219.020 ;
    END
  END FrameData_O[26]
  PIN FrameData_O[27]
    DIRECTION OUTPUT ;
    USE SIGNAL ;
    ANTENNADIFFAREA 2.724000 ;
    PORT
      LAYER Metal3 ;
        RECT 269.840 220.300 270.240 220.700 ;
    END
  END FrameData_O[27]
  PIN FrameData_O[28]
    DIRECTION OUTPUT ;
    USE SIGNAL ;
    ANTENNADIFFAREA 2.724000 ;
    PORT
      LAYER Metal3 ;
        RECT 269.840 221.980 270.240 222.380 ;
    END
  END FrameData_O[28]
  PIN FrameData_O[29]
    DIRECTION OUTPUT ;
    USE SIGNAL ;
    ANTENNADIFFAREA 2.724000 ;
    PORT
      LAYER Metal3 ;
        RECT 269.840 223.660 270.240 224.060 ;
    END
  END FrameData_O[29]
  PIN FrameData_O[2]
    DIRECTION OUTPUT ;
    USE SIGNAL ;
    ANTENNADIFFAREA 2.724000 ;
    PORT
      LAYER Metal3 ;
        RECT 269.840 178.300 270.240 178.700 ;
    END
  END FrameData_O[2]
  PIN FrameData_O[30]
    DIRECTION OUTPUT ;
    USE SIGNAL ;
    ANTENNADIFFAREA 2.724000 ;
    PORT
      LAYER Metal3 ;
        RECT 269.840 225.340 270.240 225.740 ;
    END
  END FrameData_O[30]
  PIN FrameData_O[31]
    DIRECTION OUTPUT ;
    USE SIGNAL ;
    ANTENNADIFFAREA 2.724000 ;
    PORT
      LAYER Metal3 ;
        RECT 269.840 227.020 270.240 227.420 ;
    END
  END FrameData_O[31]
  PIN FrameData_O[3]
    DIRECTION OUTPUT ;
    USE SIGNAL ;
    ANTENNADIFFAREA 2.724000 ;
    PORT
      LAYER Metal3 ;
        RECT 269.840 179.980 270.240 180.380 ;
    END
  END FrameData_O[3]
  PIN FrameData_O[4]
    DIRECTION OUTPUT ;
    USE SIGNAL ;
    ANTENNADIFFAREA 2.724000 ;
    PORT
      LAYER Metal3 ;
        RECT 269.840 181.660 270.240 182.060 ;
    END
  END FrameData_O[4]
  PIN FrameData_O[5]
    DIRECTION OUTPUT ;
    USE SIGNAL ;
    ANTENNADIFFAREA 2.724000 ;
    PORT
      LAYER Metal3 ;
        RECT 269.840 183.340 270.240 183.740 ;
    END
  END FrameData_O[5]
  PIN FrameData_O[6]
    DIRECTION OUTPUT ;
    USE SIGNAL ;
    ANTENNADIFFAREA 2.724000 ;
    PORT
      LAYER Metal3 ;
        RECT 269.840 185.020 270.240 185.420 ;
    END
  END FrameData_O[6]
  PIN FrameData_O[7]
    DIRECTION OUTPUT ;
    USE SIGNAL ;
    ANTENNADIFFAREA 2.724000 ;
    PORT
      LAYER Metal3 ;
        RECT 269.840 186.700 270.240 187.100 ;
    END
  END FrameData_O[7]
  PIN FrameData_O[8]
    DIRECTION OUTPUT ;
    USE SIGNAL ;
    ANTENNADIFFAREA 2.724000 ;
    PORT
      LAYER Metal3 ;
        RECT 269.840 188.380 270.240 188.780 ;
    END
  END FrameData_O[8]
  PIN FrameData_O[9]
    DIRECTION OUTPUT ;
    USE SIGNAL ;
    ANTENNADIFFAREA 2.724000 ;
    PORT
      LAYER Metal3 ;
        RECT 269.840 190.060 270.240 190.460 ;
    END
  END FrameData_O[9]
  PIN FrameStrobe[0]
    DIRECTION INPUT ;
    USE SIGNAL ;
    ANTENNAGATEAREA 11.745500 ;
    PORT
      LAYER Metal2 ;
        RECT 230.680 0.000 231.080 0.400 ;
    END
  END FrameStrobe[0]
  PIN FrameStrobe[10]
    DIRECTION INPUT ;
    USE SIGNAL ;
    ANTENNAGATEAREA 11.745500 ;
    PORT
      LAYER Metal2 ;
        RECT 249.880 0.000 250.280 0.400 ;
    END
  END FrameStrobe[10]
  PIN FrameStrobe[11]
    DIRECTION INPUT ;
    USE SIGNAL ;
    ANTENNAGATEAREA 1.719900 ;
    PORT
      LAYER Metal2 ;
        RECT 251.800 0.000 252.200 0.400 ;
    END
  END FrameStrobe[11]
  PIN FrameStrobe[12]
    DIRECTION INPUT ;
    USE SIGNAL ;
    ANTENNAGATEAREA 1.719900 ;
    PORT
      LAYER Metal2 ;
        RECT 253.720 0.000 254.120 0.400 ;
    END
  END FrameStrobe[12]
  PIN FrameStrobe[13]
    DIRECTION INPUT ;
    USE SIGNAL ;
    ANTENNAGATEAREA 1.719900 ;
    PORT
      LAYER Metal2 ;
        RECT 255.640 0.000 256.040 0.400 ;
    END
  END FrameStrobe[13]
  PIN FrameStrobe[14]
    DIRECTION INPUT ;
    USE SIGNAL ;
    ANTENNAGATEAREA 1.142700 ;
    ANTENNADIFFAREA 36.277199 ;
    PORT
      LAYER Metal2 ;
        RECT 257.560 0.000 257.960 0.400 ;
    END
  END FrameStrobe[14]
  PIN FrameStrobe[15]
    DIRECTION INPUT ;
    USE SIGNAL ;
    ANTENNAGATEAREA 0.950300 ;
    PORT
      LAYER Metal2 ;
        RECT 259.480 0.000 259.880 0.400 ;
    END
  END FrameStrobe[15]
  PIN FrameStrobe[16]
    DIRECTION INPUT ;
    USE SIGNAL ;
    ANTENNAGATEAREA 0.950300 ;
    PORT
      LAYER Metal2 ;
        RECT 261.400 0.000 261.800 0.400 ;
    END
  END FrameStrobe[16]
  PIN FrameStrobe[17]
    DIRECTION INPUT ;
    USE SIGNAL ;
    ANTENNAGATEAREA 0.757900 ;
    ANTENNADIFFAREA 32.246399 ;
    PORT
      LAYER Metal2 ;
        RECT 263.320 0.000 263.720 0.400 ;
    END
  END FrameStrobe[17]
  PIN FrameStrobe[18]
    DIRECTION INPUT ;
    USE SIGNAL ;
    ANTENNAGATEAREA 0.757900 ;
    ANTENNADIFFAREA 8.061600 ;
    PORT
      LAYER Metal2 ;
        RECT 265.240 0.000 265.640 0.400 ;
    END
  END FrameStrobe[18]
  PIN FrameStrobe[19]
    DIRECTION INPUT ;
    USE SIGNAL ;
    ANTENNAGATEAREA 0.757900 ;
    PORT
      LAYER Metal2 ;
        RECT 267.160 0.000 267.560 0.400 ;
    END
  END FrameStrobe[19]
  PIN FrameStrobe[1]
    DIRECTION INPUT ;
    USE SIGNAL ;
    ANTENNAGATEAREA 11.745500 ;
    PORT
      LAYER Metal2 ;
        RECT 232.600 0.000 233.000 0.400 ;
    END
  END FrameStrobe[1]
  PIN FrameStrobe[2]
    DIRECTION INPUT ;
    USE SIGNAL ;
    ANTENNAGATEAREA 11.745500 ;
    PORT
      LAYER Metal2 ;
        RECT 234.520 0.000 234.920 0.400 ;
    END
  END FrameStrobe[2]
  PIN FrameStrobe[3]
    DIRECTION INPUT ;
    USE SIGNAL ;
    ANTENNAGATEAREA 11.745500 ;
    PORT
      LAYER Metal2 ;
        RECT 236.440 0.000 236.840 0.400 ;
    END
  END FrameStrobe[3]
  PIN FrameStrobe[4]
    DIRECTION INPUT ;
    USE SIGNAL ;
    ANTENNAGATEAREA 11.745500 ;
    PORT
      LAYER Metal2 ;
        RECT 238.360 0.000 238.760 0.400 ;
    END
  END FrameStrobe[4]
  PIN FrameStrobe[5]
    DIRECTION INPUT ;
    USE SIGNAL ;
    ANTENNAGATEAREA 11.745500 ;
    PORT
      LAYER Metal2 ;
        RECT 240.280 0.000 240.680 0.400 ;
    END
  END FrameStrobe[5]
  PIN FrameStrobe[6]
    DIRECTION INPUT ;
    USE SIGNAL ;
    ANTENNAGATEAREA 11.745500 ;
    PORT
      LAYER Metal2 ;
        RECT 242.200 0.000 242.600 0.400 ;
    END
  END FrameStrobe[6]
  PIN FrameStrobe[7]
    DIRECTION INPUT ;
    USE SIGNAL ;
    ANTENNAGATEAREA 11.745500 ;
    PORT
      LAYER Metal2 ;
        RECT 244.120 0.000 244.520 0.400 ;
    END
  END FrameStrobe[7]
  PIN FrameStrobe[8]
    DIRECTION INPUT ;
    USE SIGNAL ;
    ANTENNAGATEAREA 11.745500 ;
    PORT
      LAYER Metal2 ;
        RECT 246.040 0.000 246.440 0.400 ;
    END
  END FrameStrobe[8]
  PIN FrameStrobe[9]
    DIRECTION INPUT ;
    USE SIGNAL ;
    ANTENNAGATEAREA 11.745500 ;
    PORT
      LAYER Metal2 ;
        RECT 247.960 0.000 248.360 0.400 ;
    END
  END FrameStrobe[9]
  PIN FrameStrobe_O[0]
    DIRECTION OUTPUT ;
    USE SIGNAL ;
    ANTENNADIFFAREA 2.724000 ;
    PORT
      LAYER Metal2 ;
        RECT 230.680 229.760 231.080 230.160 ;
    END
  END FrameStrobe_O[0]
  PIN FrameStrobe_O[10]
    DIRECTION OUTPUT ;
    USE SIGNAL ;
    ANTENNADIFFAREA 2.724000 ;
    PORT
      LAYER Metal2 ;
        RECT 249.880 229.760 250.280 230.160 ;
    END
  END FrameStrobe_O[10]
  PIN FrameStrobe_O[11]
    DIRECTION OUTPUT ;
    USE SIGNAL ;
    ANTENNADIFFAREA 2.724000 ;
    PORT
      LAYER Metal2 ;
        RECT 251.800 229.760 252.200 230.160 ;
    END
  END FrameStrobe_O[11]
  PIN FrameStrobe_O[12]
    DIRECTION OUTPUT ;
    USE SIGNAL ;
    ANTENNADIFFAREA 2.724000 ;
    PORT
      LAYER Metal2 ;
        RECT 253.720 229.760 254.120 230.160 ;
    END
  END FrameStrobe_O[12]
  PIN FrameStrobe_O[13]
    DIRECTION OUTPUT ;
    USE SIGNAL ;
    ANTENNADIFFAREA 2.724000 ;
    PORT
      LAYER Metal2 ;
        RECT 255.640 229.760 256.040 230.160 ;
    END
  END FrameStrobe_O[13]
  PIN FrameStrobe_O[14]
    DIRECTION OUTPUT ;
    USE SIGNAL ;
    ANTENNADIFFAREA 2.724000 ;
    PORT
      LAYER Metal2 ;
        RECT 257.560 229.760 257.960 230.160 ;
    END
  END FrameStrobe_O[14]
  PIN FrameStrobe_O[15]
    DIRECTION OUTPUT ;
    USE SIGNAL ;
    ANTENNADIFFAREA 2.724000 ;
    PORT
      LAYER Metal2 ;
        RECT 259.480 229.760 259.880 230.160 ;
    END
  END FrameStrobe_O[15]
  PIN FrameStrobe_O[16]
    DIRECTION OUTPUT ;
    USE SIGNAL ;
    ANTENNADIFFAREA 2.724000 ;
    PORT
      LAYER Metal2 ;
        RECT 261.400 229.760 261.800 230.160 ;
    END
  END FrameStrobe_O[16]
  PIN FrameStrobe_O[17]
    DIRECTION OUTPUT ;
    USE SIGNAL ;
    ANTENNADIFFAREA 2.724000 ;
    PORT
      LAYER Metal2 ;
        RECT 263.320 229.760 263.720 230.160 ;
    END
  END FrameStrobe_O[17]
  PIN FrameStrobe_O[18]
    DIRECTION OUTPUT ;
    USE SIGNAL ;
    ANTENNADIFFAREA 2.724000 ;
    PORT
      LAYER Metal2 ;
        RECT 265.240 229.760 265.640 230.160 ;
    END
  END FrameStrobe_O[18]
  PIN FrameStrobe_O[19]
    DIRECTION OUTPUT ;
    USE SIGNAL ;
    ANTENNADIFFAREA 2.724000 ;
    PORT
      LAYER Metal2 ;
        RECT 267.160 229.760 267.560 230.160 ;
    END
  END FrameStrobe_O[19]
  PIN FrameStrobe_O[1]
    DIRECTION OUTPUT ;
    USE SIGNAL ;
    ANTENNADIFFAREA 2.724000 ;
    PORT
      LAYER Metal2 ;
        RECT 232.600 229.760 233.000 230.160 ;
    END
  END FrameStrobe_O[1]
  PIN FrameStrobe_O[2]
    DIRECTION OUTPUT ;
    USE SIGNAL ;
    ANTENNADIFFAREA 2.724000 ;
    PORT
      LAYER Metal2 ;
        RECT 234.520 229.760 234.920 230.160 ;
    END
  END FrameStrobe_O[2]
  PIN FrameStrobe_O[3]
    DIRECTION OUTPUT ;
    USE SIGNAL ;
    ANTENNADIFFAREA 2.724000 ;
    PORT
      LAYER Metal2 ;
        RECT 236.440 229.760 236.840 230.160 ;
    END
  END FrameStrobe_O[3]
  PIN FrameStrobe_O[4]
    DIRECTION OUTPUT ;
    USE SIGNAL ;
    ANTENNADIFFAREA 2.724000 ;
    PORT
      LAYER Metal2 ;
        RECT 238.360 229.760 238.760 230.160 ;
    END
  END FrameStrobe_O[4]
  PIN FrameStrobe_O[5]
    DIRECTION OUTPUT ;
    USE SIGNAL ;
    ANTENNADIFFAREA 2.724000 ;
    PORT
      LAYER Metal2 ;
        RECT 240.280 229.760 240.680 230.160 ;
    END
  END FrameStrobe_O[5]
  PIN FrameStrobe_O[6]
    DIRECTION OUTPUT ;
    USE SIGNAL ;
    ANTENNADIFFAREA 2.724000 ;
    PORT
      LAYER Metal2 ;
        RECT 242.200 229.760 242.600 230.160 ;
    END
  END FrameStrobe_O[6]
  PIN FrameStrobe_O[7]
    DIRECTION OUTPUT ;
    USE SIGNAL ;
    ANTENNADIFFAREA 2.724000 ;
    PORT
      LAYER Metal2 ;
        RECT 244.120 229.760 244.520 230.160 ;
    END
  END FrameStrobe_O[7]
  PIN FrameStrobe_O[8]
    DIRECTION OUTPUT ;
    USE SIGNAL ;
    ANTENNADIFFAREA 2.724000 ;
    PORT
      LAYER Metal2 ;
        RECT 246.040 229.760 246.440 230.160 ;
    END
  END FrameStrobe_O[8]
  PIN FrameStrobe_O[9]
    DIRECTION OUTPUT ;
    USE SIGNAL ;
    ANTENNADIFFAREA 2.724000 ;
    PORT
      LAYER Metal2 ;
        RECT 247.960 229.760 248.360 230.160 ;
    END
  END FrameStrobe_O[9]
  PIN N1BEG[0]
    DIRECTION OUTPUT ;
    USE SIGNAL ;
    ANTENNADIFFAREA 2.724000 ;
    PORT
      LAYER Metal2 ;
        RECT 2.200 229.760 2.600 230.160 ;
    END
  END N1BEG[0]
  PIN N1BEG[1]
    DIRECTION OUTPUT ;
    USE SIGNAL ;
    ANTENNADIFFAREA 2.724000 ;
    PORT
      LAYER Metal2 ;
        RECT 4.120 229.760 4.520 230.160 ;
    END
  END N1BEG[1]
  PIN N1BEG[2]
    DIRECTION OUTPUT ;
    USE SIGNAL ;
    ANTENNADIFFAREA 2.724000 ;
    PORT
      LAYER Metal2 ;
        RECT 6.040 229.760 6.440 230.160 ;
    END
  END N1BEG[2]
  PIN N1BEG[3]
    DIRECTION OUTPUT ;
    USE SIGNAL ;
    ANTENNADIFFAREA 2.724000 ;
    PORT
      LAYER Metal2 ;
        RECT 7.960 229.760 8.360 230.160 ;
    END
  END N1BEG[3]
  PIN N1END[0]
    DIRECTION INPUT ;
    USE SIGNAL ;
    ANTENNAGATEAREA 1.492400 ;
    PORT
      LAYER Metal2 ;
        RECT 2.200 0.000 2.600 0.400 ;
    END
  END N1END[0]
  PIN N1END[1]
    DIRECTION INPUT ;
    USE SIGNAL ;
    ANTENNAGATEAREA 1.918800 ;
    PORT
      LAYER Metal2 ;
        RECT 4.120 0.000 4.520 0.400 ;
    END
  END N1END[1]
  PIN N1END[2]
    DIRECTION INPUT ;
    USE SIGNAL ;
    ANTENNAGATEAREA 1.492400 ;
    PORT
      LAYER Metal2 ;
        RECT 6.040 0.000 6.440 0.400 ;
    END
  END N1END[2]
  PIN N1END[3]
    DIRECTION INPUT ;
    USE SIGNAL ;
    ANTENNAGATEAREA 1.492400 ;
    PORT
      LAYER Metal2 ;
        RECT 7.960 0.000 8.360 0.400 ;
    END
  END N1END[3]
  PIN N2BEG[0]
    DIRECTION OUTPUT ;
    USE SIGNAL ;
    ANTENNADIFFAREA 2.724000 ;
    PORT
      LAYER Metal2 ;
        RECT 10.840 229.760 11.240 230.160 ;
    END
  END N2BEG[0]
  PIN N2BEG[1]
    DIRECTION OUTPUT ;
    USE SIGNAL ;
    ANTENNADIFFAREA 2.724000 ;
    PORT
      LAYER Metal2 ;
        RECT 12.760 229.760 13.160 230.160 ;
    END
  END N2BEG[1]
  PIN N2BEG[2]
    DIRECTION OUTPUT ;
    USE SIGNAL ;
    ANTENNADIFFAREA 2.724000 ;
    PORT
      LAYER Metal2 ;
        RECT 14.680 229.760 15.080 230.160 ;
    END
  END N2BEG[2]
  PIN N2BEG[3]
    DIRECTION OUTPUT ;
    USE SIGNAL ;
    ANTENNADIFFAREA 2.724000 ;
    PORT
      LAYER Metal2 ;
        RECT 16.600 229.760 17.000 230.160 ;
    END
  END N2BEG[3]
  PIN N2BEG[4]
    DIRECTION OUTPUT ;
    USE SIGNAL ;
    ANTENNADIFFAREA 2.724000 ;
    PORT
      LAYER Metal2 ;
        RECT 18.520 229.760 18.920 230.160 ;
    END
  END N2BEG[4]
  PIN N2BEG[5]
    DIRECTION OUTPUT ;
    USE SIGNAL ;
    ANTENNADIFFAREA 2.724000 ;
    PORT
      LAYER Metal2 ;
        RECT 20.440 229.760 20.840 230.160 ;
    END
  END N2BEG[5]
  PIN N2BEG[6]
    DIRECTION OUTPUT ;
    USE SIGNAL ;
    ANTENNADIFFAREA 2.724000 ;
    PORT
      LAYER Metal2 ;
        RECT 22.360 229.760 22.760 230.160 ;
    END
  END N2BEG[6]
  PIN N2BEG[7]
    DIRECTION OUTPUT ;
    USE SIGNAL ;
    ANTENNADIFFAREA 2.724000 ;
    PORT
      LAYER Metal2 ;
        RECT 24.280 229.760 24.680 230.160 ;
    END
  END N2BEG[7]
  PIN N2BEGb[0]
    DIRECTION OUTPUT ;
    USE SIGNAL ;
    ANTENNADIFFAREA 2.724000 ;
    PORT
      LAYER Metal2 ;
        RECT 27.160 229.760 27.560 230.160 ;
    END
  END N2BEGb[0]
  PIN N2BEGb[1]
    DIRECTION OUTPUT ;
    USE SIGNAL ;
    ANTENNADIFFAREA 2.724000 ;
    PORT
      LAYER Metal2 ;
        RECT 29.080 229.760 29.480 230.160 ;
    END
  END N2BEGb[1]
  PIN N2BEGb[2]
    DIRECTION OUTPUT ;
    USE SIGNAL ;
    ANTENNADIFFAREA 2.724000 ;
    PORT
      LAYER Metal2 ;
        RECT 31.000 229.760 31.400 230.160 ;
    END
  END N2BEGb[2]
  PIN N2BEGb[3]
    DIRECTION OUTPUT ;
    USE SIGNAL ;
    ANTENNADIFFAREA 2.724000 ;
    PORT
      LAYER Metal2 ;
        RECT 32.920 229.760 33.320 230.160 ;
    END
  END N2BEGb[3]
  PIN N2BEGb[4]
    DIRECTION OUTPUT ;
    USE SIGNAL ;
    ANTENNADIFFAREA 2.724000 ;
    PORT
      LAYER Metal2 ;
        RECT 34.840 229.760 35.240 230.160 ;
    END
  END N2BEGb[4]
  PIN N2BEGb[5]
    DIRECTION OUTPUT ;
    USE SIGNAL ;
    ANTENNADIFFAREA 2.724000 ;
    PORT
      LAYER Metal2 ;
        RECT 36.760 229.760 37.160 230.160 ;
    END
  END N2BEGb[5]
  PIN N2BEGb[6]
    DIRECTION OUTPUT ;
    USE SIGNAL ;
    ANTENNADIFFAREA 2.724000 ;
    PORT
      LAYER Metal2 ;
        RECT 38.680 229.760 39.080 230.160 ;
    END
  END N2BEGb[6]
  PIN N2BEGb[7]
    DIRECTION OUTPUT ;
    USE SIGNAL ;
    ANTENNADIFFAREA 2.724000 ;
    PORT
      LAYER Metal2 ;
        RECT 40.600 229.760 41.000 230.160 ;
    END
  END N2BEGb[7]
  PIN N2END[0]
    DIRECTION INPUT ;
    USE SIGNAL ;
    ANTENNAGATEAREA 1.292200 ;
    ANTENNADIFFAREA 12.092400 ;
    PORT
      LAYER Metal2 ;
        RECT 27.160 0.000 27.560 0.400 ;
    END
  END N2END[0]
  PIN N2END[1]
    DIRECTION INPUT ;
    USE SIGNAL ;
    ANTENNAGATEAREA 1.505400 ;
    PORT
      LAYER Metal2 ;
        RECT 29.080 0.000 29.480 0.400 ;
    END
  END N2END[1]
  PIN N2END[2]
    DIRECTION INPUT ;
    USE SIGNAL ;
    ANTENNAGATEAREA 1.918800 ;
    PORT
      LAYER Metal2 ;
        RECT 31.000 0.000 31.400 0.400 ;
    END
  END N2END[2]
  PIN N2END[3]
    DIRECTION INPUT ;
    USE SIGNAL ;
    ANTENNAGATEAREA 1.918800 ;
    PORT
      LAYER Metal2 ;
        RECT 32.920 0.000 33.320 0.400 ;
    END
  END N2END[3]
  PIN N2END[4]
    DIRECTION INPUT ;
    USE SIGNAL ;
    ANTENNAGATEAREA 1.918800 ;
    PORT
      LAYER Metal2 ;
        RECT 34.840 0.000 35.240 0.400 ;
    END
  END N2END[4]
  PIN N2END[5]
    DIRECTION INPUT ;
    USE SIGNAL ;
    ANTENNAGATEAREA 1.492400 ;
    PORT
      LAYER Metal2 ;
        RECT 36.760 0.000 37.160 0.400 ;
    END
  END N2END[5]
  PIN N2END[6]
    DIRECTION INPUT ;
    USE SIGNAL ;
    ANTENNAGATEAREA 1.492400 ;
    PORT
      LAYER Metal2 ;
        RECT 38.680 0.000 39.080 0.400 ;
    END
  END N2END[6]
  PIN N2END[7]
    DIRECTION INPUT ;
    USE SIGNAL ;
    ANTENNAGATEAREA 1.492400 ;
    PORT
      LAYER Metal2 ;
        RECT 40.600 0.000 41.000 0.400 ;
    END
  END N2END[7]
  PIN N2MID[0]
    DIRECTION INPUT ;
    USE SIGNAL ;
    ANTENNAGATEAREA 2.325700 ;
    PORT
      LAYER Metal2 ;
        RECT 10.840 0.000 11.240 0.400 ;
    END
  END N2MID[0]
  PIN N2MID[1]
    DIRECTION INPUT ;
    USE SIGNAL ;
    ANTENNAGATEAREA 1.673100 ;
    PORT
      LAYER Metal2 ;
        RECT 12.760 0.000 13.160 0.400 ;
    END
  END N2MID[1]
  PIN N2MID[2]
    DIRECTION INPUT ;
    USE SIGNAL ;
    ANTENNAGATEAREA 1.246700 ;
    PORT
      LAYER Metal2 ;
        RECT 14.680 0.000 15.080 0.400 ;
    END
  END N2MID[2]
  PIN N2MID[3]
    DIRECTION INPUT ;
    USE SIGNAL ;
    ANTENNAGATEAREA 1.246700 ;
    PORT
      LAYER Metal2 ;
        RECT 16.600 0.000 17.000 0.400 ;
    END
  END N2MID[3]
  PIN N2MID[4]
    DIRECTION INPUT ;
    USE SIGNAL ;
    ANTENNAGATEAREA 1.459900 ;
    ANTENNADIFFAREA 16.123199 ;
    PORT
      LAYER Metal2 ;
        RECT 18.520 0.000 18.920 0.400 ;
    END
  END N2MID[4]
  PIN N2MID[5]
    DIRECTION INPUT ;
    USE SIGNAL ;
    ANTENNAGATEAREA 1.459900 ;
    ANTENNADIFFAREA 16.123199 ;
    PORT
      LAYER Metal2 ;
        RECT 20.440 0.000 20.840 0.400 ;
    END
  END N2MID[5]
  PIN N2MID[6]
    DIRECTION INPUT ;
    USE SIGNAL ;
    ANTENNAGATEAREA 1.246700 ;
    PORT
      LAYER Metal2 ;
        RECT 22.360 0.000 22.760 0.400 ;
    END
  END N2MID[6]
  PIN N2MID[7]
    DIRECTION INPUT ;
    USE SIGNAL ;
    ANTENNAGATEAREA 1.673100 ;
    PORT
      LAYER Metal2 ;
        RECT 24.280 0.000 24.680 0.400 ;
    END
  END N2MID[7]
  PIN N4BEG[0]
    DIRECTION OUTPUT ;
    USE SIGNAL ;
    ANTENNADIFFAREA 2.724000 ;
    PORT
      LAYER Metal2 ;
        RECT 45.400 229.760 45.800 230.160 ;
    END
  END N4BEG[0]
  PIN N4BEG[10]
    DIRECTION OUTPUT ;
    USE SIGNAL ;
    ANTENNADIFFAREA 2.724000 ;
    PORT
      LAYER Metal2 ;
        RECT 64.600 229.760 65.000 230.160 ;
    END
  END N4BEG[10]
  PIN N4BEG[11]
    DIRECTION OUTPUT ;
    USE SIGNAL ;
    ANTENNADIFFAREA 2.724000 ;
    PORT
      LAYER Metal2 ;
        RECT 66.520 229.760 66.920 230.160 ;
    END
  END N4BEG[11]
  PIN N4BEG[12]
    DIRECTION OUTPUT ;
    USE SIGNAL ;
    ANTENNADIFFAREA 2.724000 ;
    PORT
      LAYER Metal2 ;
        RECT 68.440 229.760 68.840 230.160 ;
    END
  END N4BEG[12]
  PIN N4BEG[13]
    DIRECTION OUTPUT ;
    USE SIGNAL ;
    ANTENNADIFFAREA 2.724000 ;
    PORT
      LAYER Metal2 ;
        RECT 70.360 229.760 70.760 230.160 ;
    END
  END N4BEG[13]
  PIN N4BEG[14]
    DIRECTION OUTPUT ;
    USE SIGNAL ;
    ANTENNADIFFAREA 2.724000 ;
    PORT
      LAYER Metal2 ;
        RECT 72.280 229.760 72.680 230.160 ;
    END
  END N4BEG[14]
  PIN N4BEG[15]
    DIRECTION OUTPUT ;
    USE SIGNAL ;
    ANTENNADIFFAREA 2.724000 ;
    PORT
      LAYER Metal2 ;
        RECT 74.200 229.760 74.600 230.160 ;
    END
  END N4BEG[15]
  PIN N4BEG[1]
    DIRECTION OUTPUT ;
    USE SIGNAL ;
    ANTENNADIFFAREA 2.724000 ;
    PORT
      LAYER Metal2 ;
        RECT 47.320 229.760 47.720 230.160 ;
    END
  END N4BEG[1]
  PIN N4BEG[2]
    DIRECTION OUTPUT ;
    USE SIGNAL ;
    ANTENNADIFFAREA 2.724000 ;
    PORT
      LAYER Metal2 ;
        RECT 49.240 229.760 49.640 230.160 ;
    END
  END N4BEG[2]
  PIN N4BEG[3]
    DIRECTION OUTPUT ;
    USE SIGNAL ;
    ANTENNADIFFAREA 2.724000 ;
    PORT
      LAYER Metal2 ;
        RECT 51.160 229.760 51.560 230.160 ;
    END
  END N4BEG[3]
  PIN N4BEG[4]
    DIRECTION OUTPUT ;
    USE SIGNAL ;
    ANTENNADIFFAREA 2.724000 ;
    PORT
      LAYER Metal2 ;
        RECT 53.080 229.760 53.480 230.160 ;
    END
  END N4BEG[4]
  PIN N4BEG[5]
    DIRECTION OUTPUT ;
    USE SIGNAL ;
    ANTENNADIFFAREA 2.724000 ;
    PORT
      LAYER Metal2 ;
        RECT 55.000 229.760 55.400 230.160 ;
    END
  END N4BEG[5]
  PIN N4BEG[6]
    DIRECTION OUTPUT ;
    USE SIGNAL ;
    ANTENNADIFFAREA 2.724000 ;
    PORT
      LAYER Metal2 ;
        RECT 56.920 229.760 57.320 230.160 ;
    END
  END N4BEG[6]
  PIN N4BEG[7]
    DIRECTION OUTPUT ;
    USE SIGNAL ;
    ANTENNADIFFAREA 2.724000 ;
    PORT
      LAYER Metal2 ;
        RECT 58.840 229.760 59.240 230.160 ;
    END
  END N4BEG[7]
  PIN N4BEG[8]
    DIRECTION OUTPUT ;
    USE SIGNAL ;
    ANTENNADIFFAREA 2.724000 ;
    PORT
      LAYER Metal2 ;
        RECT 60.760 229.760 61.160 230.160 ;
    END
  END N4BEG[8]
  PIN N4BEG[9]
    DIRECTION OUTPUT ;
    USE SIGNAL ;
    ANTENNADIFFAREA 2.724000 ;
    PORT
      LAYER Metal2 ;
        RECT 62.680 229.760 63.080 230.160 ;
    END
  END N4BEG[9]
  PIN N4END[0]
    DIRECTION INPUT ;
    USE SIGNAL ;
    ANTENNAGATEAREA 1.718600 ;
    PORT
      LAYER Metal2 ;
        RECT 45.400 0.000 45.800 0.400 ;
    END
  END N4END[0]
  PIN N4END[10]
    DIRECTION INPUT ;
    USE SIGNAL ;
    ANTENNAGATEAREA 0.180700 ;
    PORT
      LAYER Metal2 ;
        RECT 64.600 0.000 65.000 0.400 ;
    END
  END N4END[10]
  PIN N4END[11]
    DIRECTION INPUT ;
    USE SIGNAL ;
    ANTENNAGATEAREA 0.180700 ;
    PORT
      LAYER Metal2 ;
        RECT 66.520 0.000 66.920 0.400 ;
    END
  END N4END[11]
  PIN N4END[12]
    DIRECTION INPUT ;
    USE SIGNAL ;
    ANTENNAGATEAREA 0.180700 ;
    PORT
      LAYER Metal2 ;
        RECT 68.440 0.000 68.840 0.400 ;
    END
  END N4END[12]
  PIN N4END[13]
    DIRECTION INPUT ;
    USE SIGNAL ;
    ANTENNAGATEAREA 0.180700 ;
    PORT
      LAYER Metal2 ;
        RECT 70.360 0.000 70.760 0.400 ;
    END
  END N4END[13]
  PIN N4END[14]
    DIRECTION INPUT ;
    USE SIGNAL ;
    ANTENNAGATEAREA 0.180700 ;
    PORT
      LAYER Metal2 ;
        RECT 72.280 0.000 72.680 0.400 ;
    END
  END N4END[14]
  PIN N4END[15]
    DIRECTION INPUT ;
    USE SIGNAL ;
    ANTENNAGATEAREA 0.180700 ;
    ANTENNADIFFAREA 2.015400 ;
    PORT
      LAYER Metal2 ;
        RECT 74.200 0.000 74.600 0.400 ;
    END
  END N4END[15]
  PIN N4END[1]
    DIRECTION INPUT ;
    USE SIGNAL ;
    ANTENNAGATEAREA 1.718600 ;
    PORT
      LAYER Metal2 ;
        RECT 47.320 0.000 47.720 0.400 ;
    END
  END N4END[1]
  PIN N4END[2]
    DIRECTION INPUT ;
    USE SIGNAL ;
    ANTENNAGATEAREA 1.705600 ;
    PORT
      LAYER Metal2 ;
        RECT 49.240 0.000 49.640 0.400 ;
    END
  END N4END[2]
  PIN N4END[3]
    DIRECTION INPUT ;
    USE SIGNAL ;
    ANTENNAGATEAREA 1.492400 ;
    PORT
      LAYER Metal2 ;
        RECT 51.160 0.000 51.560 0.400 ;
    END
  END N4END[3]
  PIN N4END[4]
    DIRECTION INPUT ;
    USE SIGNAL ;
    ANTENNAGATEAREA 0.180700 ;
    PORT
      LAYER Metal2 ;
        RECT 53.080 0.000 53.480 0.400 ;
    END
  END N4END[4]
  PIN N4END[5]
    DIRECTION INPUT ;
    USE SIGNAL ;
    ANTENNAGATEAREA 0.180700 ;
    PORT
      LAYER Metal2 ;
        RECT 55.000 0.000 55.400 0.400 ;
    END
  END N4END[5]
  PIN N4END[6]
    DIRECTION INPUT ;
    USE SIGNAL ;
    ANTENNAGATEAREA 0.180700 ;
    PORT
      LAYER Metal2 ;
        RECT 56.920 0.000 57.320 0.400 ;
    END
  END N4END[6]
  PIN N4END[7]
    DIRECTION INPUT ;
    USE SIGNAL ;
    ANTENNAGATEAREA 0.180700 ;
    PORT
      LAYER Metal2 ;
        RECT 58.840 0.000 59.240 0.400 ;
    END
  END N4END[7]
  PIN N4END[8]
    DIRECTION INPUT ;
    USE SIGNAL ;
    ANTENNAGATEAREA 0.180700 ;
    PORT
      LAYER Metal2 ;
        RECT 60.760 0.000 61.160 0.400 ;
    END
  END N4END[8]
  PIN N4END[9]
    DIRECTION INPUT ;
    USE SIGNAL ;
    ANTENNAGATEAREA 0.180700 ;
    PORT
      LAYER Metal2 ;
        RECT 62.680 0.000 63.080 0.400 ;
    END
  END N4END[9]
  PIN NN4BEG[0]
    DIRECTION OUTPUT ;
    USE SIGNAL ;
    ANTENNADIFFAREA 2.724000 ;
    PORT
      LAYER Metal2 ;
        RECT 79.960 229.760 80.360 230.160 ;
    END
  END NN4BEG[0]
  PIN NN4BEG[10]
    DIRECTION OUTPUT ;
    USE SIGNAL ;
    ANTENNADIFFAREA 2.724000 ;
    PORT
      LAYER Metal2 ;
        RECT 99.160 229.760 99.560 230.160 ;
    END
  END NN4BEG[10]
  PIN NN4BEG[11]
    DIRECTION OUTPUT ;
    USE SIGNAL ;
    ANTENNADIFFAREA 2.724000 ;
    PORT
      LAYER Metal2 ;
        RECT 101.080 229.760 101.480 230.160 ;
    END
  END NN4BEG[11]
  PIN NN4BEG[12]
    DIRECTION OUTPUT ;
    USE SIGNAL ;
    ANTENNADIFFAREA 2.724000 ;
    PORT
      LAYER Metal2 ;
        RECT 103.000 229.760 103.400 230.160 ;
    END
  END NN4BEG[12]
  PIN NN4BEG[13]
    DIRECTION OUTPUT ;
    USE SIGNAL ;
    ANTENNADIFFAREA 2.724000 ;
    PORT
      LAYER Metal2 ;
        RECT 104.920 229.760 105.320 230.160 ;
    END
  END NN4BEG[13]
  PIN NN4BEG[14]
    DIRECTION OUTPUT ;
    USE SIGNAL ;
    ANTENNADIFFAREA 2.724000 ;
    PORT
      LAYER Metal2 ;
        RECT 106.840 229.760 107.240 230.160 ;
    END
  END NN4BEG[14]
  PIN NN4BEG[15]
    DIRECTION OUTPUT ;
    USE SIGNAL ;
    ANTENNADIFFAREA 2.724000 ;
    PORT
      LAYER Metal2 ;
        RECT 108.760 229.760 109.160 230.160 ;
    END
  END NN4BEG[15]
  PIN NN4BEG[1]
    DIRECTION OUTPUT ;
    USE SIGNAL ;
    ANTENNADIFFAREA 2.724000 ;
    PORT
      LAYER Metal2 ;
        RECT 81.880 229.760 82.280 230.160 ;
    END
  END NN4BEG[1]
  PIN NN4BEG[2]
    DIRECTION OUTPUT ;
    USE SIGNAL ;
    ANTENNADIFFAREA 2.724000 ;
    PORT
      LAYER Metal2 ;
        RECT 83.800 229.760 84.200 230.160 ;
    END
  END NN4BEG[2]
  PIN NN4BEG[3]
    DIRECTION OUTPUT ;
    USE SIGNAL ;
    ANTENNADIFFAREA 2.724000 ;
    PORT
      LAYER Metal2 ;
        RECT 85.720 229.760 86.120 230.160 ;
    END
  END NN4BEG[3]
  PIN NN4BEG[4]
    DIRECTION OUTPUT ;
    USE SIGNAL ;
    ANTENNADIFFAREA 2.724000 ;
    PORT
      LAYER Metal2 ;
        RECT 87.640 229.760 88.040 230.160 ;
    END
  END NN4BEG[4]
  PIN NN4BEG[5]
    DIRECTION OUTPUT ;
    USE SIGNAL ;
    ANTENNADIFFAREA 2.724000 ;
    PORT
      LAYER Metal2 ;
        RECT 89.560 229.760 89.960 230.160 ;
    END
  END NN4BEG[5]
  PIN NN4BEG[6]
    DIRECTION OUTPUT ;
    USE SIGNAL ;
    ANTENNADIFFAREA 2.724000 ;
    PORT
      LAYER Metal2 ;
        RECT 91.480 229.760 91.880 230.160 ;
    END
  END NN4BEG[6]
  PIN NN4BEG[7]
    DIRECTION OUTPUT ;
    USE SIGNAL ;
    ANTENNADIFFAREA 2.724000 ;
    PORT
      LAYER Metal2 ;
        RECT 93.400 229.760 93.800 230.160 ;
    END
  END NN4BEG[7]
  PIN NN4BEG[8]
    DIRECTION OUTPUT ;
    USE SIGNAL ;
    ANTENNADIFFAREA 2.724000 ;
    PORT
      LAYER Metal2 ;
        RECT 95.320 229.760 95.720 230.160 ;
    END
  END NN4BEG[8]
  PIN NN4BEG[9]
    DIRECTION OUTPUT ;
    USE SIGNAL ;
    ANTENNADIFFAREA 2.724000 ;
    PORT
      LAYER Metal2 ;
        RECT 97.240 229.760 97.640 230.160 ;
    END
  END NN4BEG[9]
  PIN NN4END[0]
    DIRECTION INPUT ;
    USE SIGNAL ;
    ANTENNAGATEAREA 1.918800 ;
    PORT
      LAYER Metal2 ;
        RECT 79.960 0.000 80.360 0.400 ;
    END
  END NN4END[0]
  PIN NN4END[10]
    DIRECTION INPUT ;
    USE SIGNAL ;
    ANTENNAGATEAREA 0.180700 ;
    PORT
      LAYER Metal2 ;
        RECT 99.160 0.000 99.560 0.400 ;
    END
  END NN4END[10]
  PIN NN4END[11]
    DIRECTION INPUT ;
    USE SIGNAL ;
    ANTENNAGATEAREA 0.180700 ;
    PORT
      LAYER Metal2 ;
        RECT 101.080 0.000 101.480 0.400 ;
    END
  END NN4END[11]
  PIN NN4END[12]
    DIRECTION INPUT ;
    USE SIGNAL ;
    ANTENNAGATEAREA 0.180700 ;
    PORT
      LAYER Metal2 ;
        RECT 103.000 0.000 103.400 0.400 ;
    END
  END NN4END[12]
  PIN NN4END[13]
    DIRECTION INPUT ;
    USE SIGNAL ;
    ANTENNAGATEAREA 0.180700 ;
    PORT
      LAYER Metal2 ;
        RECT 104.920 0.000 105.320 0.400 ;
    END
  END NN4END[13]
  PIN NN4END[14]
    DIRECTION INPUT ;
    USE SIGNAL ;
    ANTENNAGATEAREA 0.180700 ;
    PORT
      LAYER Metal2 ;
        RECT 106.840 0.000 107.240 0.400 ;
    END
  END NN4END[14]
  PIN NN4END[15]
    DIRECTION INPUT ;
    USE SIGNAL ;
    ANTENNAGATEAREA 0.180700 ;
    PORT
      LAYER Metal2 ;
        RECT 108.760 0.000 109.160 0.400 ;
    END
  END NN4END[15]
  PIN NN4END[1]
    DIRECTION INPUT ;
    USE SIGNAL ;
    ANTENNAGATEAREA 1.705600 ;
    PORT
      LAYER Metal2 ;
        RECT 81.880 0.000 82.280 0.400 ;
    END
  END NN4END[1]
  PIN NN4END[2]
    DIRECTION INPUT ;
    USE SIGNAL ;
    ANTENNAGATEAREA 2.132000 ;
    PORT
      LAYER Metal2 ;
        RECT 83.800 0.000 84.200 0.400 ;
    END
  END NN4END[2]
  PIN NN4END[3]
    DIRECTION INPUT ;
    USE SIGNAL ;
    ANTENNAGATEAREA 1.492400 ;
    PORT
      LAYER Metal2 ;
        RECT 85.720 0.000 86.120 0.400 ;
    END
  END NN4END[3]
  PIN NN4END[4]
    DIRECTION INPUT ;
    USE SIGNAL ;
    ANTENNAGATEAREA 0.180700 ;
    PORT
      LAYER Metal2 ;
        RECT 87.640 0.000 88.040 0.400 ;
    END
  END NN4END[4]
  PIN NN4END[5]
    DIRECTION INPUT ;
    USE SIGNAL ;
    ANTENNAGATEAREA 0.180700 ;
    PORT
      LAYER Metal2 ;
        RECT 89.560 0.000 89.960 0.400 ;
    END
  END NN4END[5]
  PIN NN4END[6]
    DIRECTION INPUT ;
    USE SIGNAL ;
    ANTENNAGATEAREA 0.180700 ;
    PORT
      LAYER Metal2 ;
        RECT 91.480 0.000 91.880 0.400 ;
    END
  END NN4END[6]
  PIN NN4END[7]
    DIRECTION INPUT ;
    USE SIGNAL ;
    ANTENNAGATEAREA 0.180700 ;
    PORT
      LAYER Metal2 ;
        RECT 93.400 0.000 93.800 0.400 ;
    END
  END NN4END[7]
  PIN NN4END[8]
    DIRECTION INPUT ;
    USE SIGNAL ;
    ANTENNAGATEAREA 0.180700 ;
    PORT
      LAYER Metal2 ;
        RECT 95.320 0.000 95.720 0.400 ;
    END
  END NN4END[8]
  PIN NN4END[9]
    DIRECTION INPUT ;
    USE SIGNAL ;
    ANTENNAGATEAREA 0.180700 ;
    PORT
      LAYER Metal2 ;
        RECT 97.240 0.000 97.640 0.400 ;
    END
  END NN4END[9]
  PIN S1BEG[0]
    DIRECTION OUTPUT ;
    USE SIGNAL ;
    ANTENNADIFFAREA 2.724000 ;
    PORT
      LAYER Metal2 ;
        RECT 113.560 0.000 113.960 0.400 ;
    END
  END S1BEG[0]
  PIN S1BEG[1]
    DIRECTION OUTPUT ;
    USE SIGNAL ;
    ANTENNADIFFAREA 2.724000 ;
    PORT
      LAYER Metal2 ;
        RECT 115.480 0.000 115.880 0.400 ;
    END
  END S1BEG[1]
  PIN S1BEG[2]
    DIRECTION OUTPUT ;
    USE SIGNAL ;
    ANTENNADIFFAREA 2.724000 ;
    PORT
      LAYER Metal2 ;
        RECT 117.400 0.000 117.800 0.400 ;
    END
  END S1BEG[2]
  PIN S1BEG[3]
    DIRECTION OUTPUT ;
    USE SIGNAL ;
    ANTENNADIFFAREA 2.724000 ;
    PORT
      LAYER Metal2 ;
        RECT 119.320 0.000 119.720 0.400 ;
    END
  END S1BEG[3]
  PIN S1END[0]
    DIRECTION INPUT ;
    USE SIGNAL ;
    ANTENNAGATEAREA 1.492400 ;
    PORT
      LAYER Metal2 ;
        RECT 113.560 229.760 113.960 230.160 ;
    END
  END S1END[0]
  PIN S1END[1]
    DIRECTION INPUT ;
    USE SIGNAL ;
    ANTENNAGATEAREA 1.705600 ;
    PORT
      LAYER Metal2 ;
        RECT 115.480 229.760 115.880 230.160 ;
    END
  END S1END[1]
  PIN S1END[2]
    DIRECTION INPUT ;
    USE SIGNAL ;
    ANTENNAGATEAREA 1.705600 ;
    PORT
      LAYER Metal2 ;
        RECT 117.400 229.760 117.800 230.160 ;
    END
  END S1END[2]
  PIN S1END[3]
    DIRECTION INPUT ;
    USE SIGNAL ;
    ANTENNAGATEAREA 1.279200 ;
    PORT
      LAYER Metal2 ;
        RECT 119.320 229.760 119.720 230.160 ;
    END
  END S1END[3]
  PIN S2BEG[0]
    DIRECTION OUTPUT ;
    USE SIGNAL ;
    ANTENNADIFFAREA 2.724000 ;
    PORT
      LAYER Metal2 ;
        RECT 122.200 0.000 122.600 0.400 ;
    END
  END S2BEG[0]
  PIN S2BEG[1]
    DIRECTION OUTPUT ;
    USE SIGNAL ;
    ANTENNADIFFAREA 2.724000 ;
    PORT
      LAYER Metal2 ;
        RECT 124.120 0.000 124.520 0.400 ;
    END
  END S2BEG[1]
  PIN S2BEG[2]
    DIRECTION OUTPUT ;
    USE SIGNAL ;
    ANTENNADIFFAREA 2.724000 ;
    PORT
      LAYER Metal2 ;
        RECT 126.040 0.000 126.440 0.400 ;
    END
  END S2BEG[2]
  PIN S2BEG[3]
    DIRECTION OUTPUT ;
    USE SIGNAL ;
    ANTENNADIFFAREA 2.724000 ;
    PORT
      LAYER Metal2 ;
        RECT 127.960 0.000 128.360 0.400 ;
    END
  END S2BEG[3]
  PIN S2BEG[4]
    DIRECTION OUTPUT ;
    USE SIGNAL ;
    ANTENNADIFFAREA 2.724000 ;
    PORT
      LAYER Metal2 ;
        RECT 129.880 0.000 130.280 0.400 ;
    END
  END S2BEG[4]
  PIN S2BEG[5]
    DIRECTION OUTPUT ;
    USE SIGNAL ;
    ANTENNADIFFAREA 2.724000 ;
    PORT
      LAYER Metal2 ;
        RECT 131.800 0.000 132.200 0.400 ;
    END
  END S2BEG[5]
  PIN S2BEG[6]
    DIRECTION OUTPUT ;
    USE SIGNAL ;
    ANTENNADIFFAREA 2.724000 ;
    PORT
      LAYER Metal2 ;
        RECT 133.720 0.000 134.120 0.400 ;
    END
  END S2BEG[6]
  PIN S2BEG[7]
    DIRECTION OUTPUT ;
    USE SIGNAL ;
    ANTENNADIFFAREA 2.724000 ;
    PORT
      LAYER Metal2 ;
        RECT 135.640 0.000 136.040 0.400 ;
    END
  END S2BEG[7]
  PIN S2BEGb[0]
    DIRECTION OUTPUT ;
    USE SIGNAL ;
    ANTENNADIFFAREA 2.724000 ;
    PORT
      LAYER Metal2 ;
        RECT 139.480 0.000 139.880 0.400 ;
    END
  END S2BEGb[0]
  PIN S2BEGb[1]
    DIRECTION OUTPUT ;
    USE SIGNAL ;
    ANTENNADIFFAREA 2.724000 ;
    PORT
      LAYER Metal2 ;
        RECT 141.400 0.000 141.800 0.400 ;
    END
  END S2BEGb[1]
  PIN S2BEGb[2]
    DIRECTION OUTPUT ;
    USE SIGNAL ;
    ANTENNADIFFAREA 2.724000 ;
    PORT
      LAYER Metal2 ;
        RECT 143.320 0.000 143.720 0.400 ;
    END
  END S2BEGb[2]
  PIN S2BEGb[3]
    DIRECTION OUTPUT ;
    USE SIGNAL ;
    ANTENNADIFFAREA 2.724000 ;
    PORT
      LAYER Metal2 ;
        RECT 145.240 0.000 145.640 0.400 ;
    END
  END S2BEGb[3]
  PIN S2BEGb[4]
    DIRECTION OUTPUT ;
    USE SIGNAL ;
    ANTENNADIFFAREA 2.724000 ;
    PORT
      LAYER Metal2 ;
        RECT 147.160 0.000 147.560 0.400 ;
    END
  END S2BEGb[4]
  PIN S2BEGb[5]
    DIRECTION OUTPUT ;
    USE SIGNAL ;
    ANTENNADIFFAREA 2.724000 ;
    PORT
      LAYER Metal2 ;
        RECT 149.080 0.000 149.480 0.400 ;
    END
  END S2BEGb[5]
  PIN S2BEGb[6]
    DIRECTION OUTPUT ;
    USE SIGNAL ;
    ANTENNADIFFAREA 2.724000 ;
    PORT
      LAYER Metal2 ;
        RECT 151.000 0.000 151.400 0.400 ;
    END
  END S2BEGb[6]
  PIN S2BEGb[7]
    DIRECTION OUTPUT ;
    USE SIGNAL ;
    ANTENNADIFFAREA 2.724000 ;
    PORT
      LAYER Metal2 ;
        RECT 152.920 0.000 153.320 0.400 ;
    END
  END S2BEGb[7]
  PIN S2END[0]
    DIRECTION INPUT ;
    USE SIGNAL ;
    ANTENNAGATEAREA 1.066000 ;
    PORT
      LAYER Metal2 ;
        RECT 139.480 229.760 139.880 230.160 ;
    END
  END S2END[0]
  PIN S2END[1]
    DIRECTION INPUT ;
    USE SIGNAL ;
    ANTENNAGATEAREA 1.279200 ;
    PORT
      LAYER Metal2 ;
        RECT 141.400 229.760 141.800 230.160 ;
    END
  END S2END[1]
  PIN S2END[2]
    DIRECTION INPUT ;
    USE SIGNAL ;
    ANTENNAGATEAREA 1.705600 ;
    PORT
      LAYER Metal2 ;
        RECT 143.320 229.760 143.720 230.160 ;
    END
  END S2END[2]
  PIN S2END[3]
    DIRECTION INPUT ;
    USE SIGNAL ;
    ANTENNAGATEAREA 1.918800 ;
    PORT
      LAYER Metal2 ;
        RECT 145.240 229.760 145.640 230.160 ;
    END
  END S2END[3]
  PIN S2END[4]
    DIRECTION INPUT ;
    USE SIGNAL ;
    ANTENNAGATEAREA 1.492400 ;
    PORT
      LAYER Metal2 ;
        RECT 147.160 229.760 147.560 230.160 ;
    END
  END S2END[4]
  PIN S2END[5]
    DIRECTION INPUT ;
    USE SIGNAL ;
    ANTENNAGATEAREA 1.292200 ;
    PORT
      LAYER Metal2 ;
        RECT 149.080 229.760 149.480 230.160 ;
    END
  END S2END[5]
  PIN S2END[6]
    DIRECTION INPUT ;
    USE SIGNAL ;
    ANTENNAGATEAREA 1.492400 ;
    PORT
      LAYER Metal2 ;
        RECT 151.000 229.760 151.400 230.160 ;
    END
  END S2END[6]
  PIN S2END[7]
    DIRECTION INPUT ;
    USE SIGNAL ;
    ANTENNAGATEAREA 1.492400 ;
    PORT
      LAYER Metal2 ;
        RECT 152.920 229.760 153.320 230.160 ;
    END
  END S2END[7]
  PIN S2MID[0]
    DIRECTION INPUT ;
    USE SIGNAL ;
    ANTENNAGATEAREA 1.886300 ;
    PORT
      LAYER Metal2 ;
        RECT 122.200 229.760 122.600 230.160 ;
    END
  END S2MID[0]
  PIN S2MID[1]
    DIRECTION INPUT ;
    USE SIGNAL ;
    ANTENNAGATEAREA 1.459900 ;
    PORT
      LAYER Metal2 ;
        RECT 124.120 229.760 124.520 230.160 ;
    END
  END S2MID[1]
  PIN S2MID[2]
    DIRECTION INPUT ;
    USE SIGNAL ;
    ANTENNAGATEAREA 1.459900 ;
    PORT
      LAYER Metal2 ;
        RECT 126.040 229.760 126.440 230.160 ;
    END
  END S2MID[2]
  PIN S2MID[3]
    DIRECTION INPUT ;
    USE SIGNAL ;
    ANTENNAGATEAREA 1.246700 ;
    PORT
      LAYER Metal2 ;
        RECT 127.960 229.760 128.360 230.160 ;
    END
  END S2MID[3]
  PIN S2MID[4]
    DIRECTION INPUT ;
    USE SIGNAL ;
    ANTENNAGATEAREA 1.472900 ;
    PORT
      LAYER Metal2 ;
        RECT 129.880 229.760 130.280 230.160 ;
    END
  END S2MID[4]
  PIN S2MID[5]
    DIRECTION INPUT ;
    USE SIGNAL ;
    ANTENNAGATEAREA 1.673100 ;
    PORT
      LAYER Metal2 ;
        RECT 131.800 229.760 132.200 230.160 ;
    END
  END S2MID[5]
  PIN S2MID[6]
    DIRECTION INPUT ;
    USE SIGNAL ;
    ANTENNAGATEAREA 1.459900 ;
    PORT
      LAYER Metal2 ;
        RECT 133.720 229.760 134.120 230.160 ;
    END
  END S2MID[6]
  PIN S2MID[7]
    DIRECTION INPUT ;
    USE SIGNAL ;
    ANTENNAGATEAREA 1.673100 ;
    PORT
      LAYER Metal2 ;
        RECT 135.640 229.760 136.040 230.160 ;
    END
  END S2MID[7]
  PIN S4BEG[0]
    DIRECTION OUTPUT ;
    USE SIGNAL ;
    ANTENNADIFFAREA 2.724000 ;
    PORT
      LAYER Metal2 ;
        RECT 157.720 0.000 158.120 0.400 ;
    END
  END S4BEG[0]
  PIN S4BEG[10]
    DIRECTION OUTPUT ;
    USE SIGNAL ;
    ANTENNADIFFAREA 2.724000 ;
    PORT
      LAYER Metal2 ;
        RECT 176.920 0.000 177.320 0.400 ;
    END
  END S4BEG[10]
  PIN S4BEG[11]
    DIRECTION OUTPUT ;
    USE SIGNAL ;
    ANTENNADIFFAREA 2.724000 ;
    PORT
      LAYER Metal2 ;
        RECT 178.840 0.000 179.240 0.400 ;
    END
  END S4BEG[11]
  PIN S4BEG[12]
    DIRECTION OUTPUT ;
    USE SIGNAL ;
    ANTENNADIFFAREA 2.724000 ;
    PORT
      LAYER Metal2 ;
        RECT 180.760 0.000 181.160 0.400 ;
    END
  END S4BEG[12]
  PIN S4BEG[13]
    DIRECTION OUTPUT ;
    USE SIGNAL ;
    ANTENNADIFFAREA 2.724000 ;
    PORT
      LAYER Metal2 ;
        RECT 182.680 0.000 183.080 0.400 ;
    END
  END S4BEG[13]
  PIN S4BEG[14]
    DIRECTION OUTPUT ;
    USE SIGNAL ;
    ANTENNADIFFAREA 2.724000 ;
    PORT
      LAYER Metal2 ;
        RECT 184.600 0.000 185.000 0.400 ;
    END
  END S4BEG[14]
  PIN S4BEG[15]
    DIRECTION OUTPUT ;
    USE SIGNAL ;
    ANTENNADIFFAREA 2.724000 ;
    PORT
      LAYER Metal2 ;
        RECT 186.520 0.000 186.920 0.400 ;
    END
  END S4BEG[15]
  PIN S4BEG[1]
    DIRECTION OUTPUT ;
    USE SIGNAL ;
    ANTENNADIFFAREA 2.724000 ;
    PORT
      LAYER Metal2 ;
        RECT 159.640 0.000 160.040 0.400 ;
    END
  END S4BEG[1]
  PIN S4BEG[2]
    DIRECTION OUTPUT ;
    USE SIGNAL ;
    ANTENNADIFFAREA 2.724000 ;
    PORT
      LAYER Metal2 ;
        RECT 161.560 0.000 161.960 0.400 ;
    END
  END S4BEG[2]
  PIN S4BEG[3]
    DIRECTION OUTPUT ;
    USE SIGNAL ;
    ANTENNADIFFAREA 2.724000 ;
    PORT
      LAYER Metal2 ;
        RECT 163.480 0.000 163.880 0.400 ;
    END
  END S4BEG[3]
  PIN S4BEG[4]
    DIRECTION OUTPUT ;
    USE SIGNAL ;
    ANTENNADIFFAREA 2.724000 ;
    PORT
      LAYER Metal2 ;
        RECT 165.400 0.000 165.800 0.400 ;
    END
  END S4BEG[4]
  PIN S4BEG[5]
    DIRECTION OUTPUT ;
    USE SIGNAL ;
    ANTENNADIFFAREA 2.724000 ;
    PORT
      LAYER Metal2 ;
        RECT 167.320 0.000 167.720 0.400 ;
    END
  END S4BEG[5]
  PIN S4BEG[6]
    DIRECTION OUTPUT ;
    USE SIGNAL ;
    ANTENNADIFFAREA 2.724000 ;
    PORT
      LAYER Metal2 ;
        RECT 169.240 0.000 169.640 0.400 ;
    END
  END S4BEG[6]
  PIN S4BEG[7]
    DIRECTION OUTPUT ;
    USE SIGNAL ;
    ANTENNADIFFAREA 2.724000 ;
    PORT
      LAYER Metal2 ;
        RECT 171.160 0.000 171.560 0.400 ;
    END
  END S4BEG[7]
  PIN S4BEG[8]
    DIRECTION OUTPUT ;
    USE SIGNAL ;
    ANTENNADIFFAREA 2.724000 ;
    PORT
      LAYER Metal2 ;
        RECT 173.080 0.000 173.480 0.400 ;
    END
  END S4BEG[8]
  PIN S4BEG[9]
    DIRECTION OUTPUT ;
    USE SIGNAL ;
    ANTENNADIFFAREA 2.724000 ;
    PORT
      LAYER Metal2 ;
        RECT 175.000 0.000 175.400 0.400 ;
    END
  END S4BEG[9]
  PIN S4END[0]
    DIRECTION INPUT ;
    USE SIGNAL ;
    ANTENNAGATEAREA 1.705600 ;
    PORT
      LAYER Metal2 ;
        RECT 157.720 229.760 158.120 230.160 ;
    END
  END S4END[0]
  PIN S4END[10]
    DIRECTION INPUT ;
    USE SIGNAL ;
    ANTENNAGATEAREA 0.180700 ;
    PORT
      LAYER Metal2 ;
        RECT 176.920 229.760 177.320 230.160 ;
    END
  END S4END[10]
  PIN S4END[11]
    DIRECTION INPUT ;
    USE SIGNAL ;
    ANTENNAGATEAREA 0.180700 ;
    PORT
      LAYER Metal2 ;
        RECT 178.840 229.760 179.240 230.160 ;
    END
  END S4END[11]
  PIN S4END[12]
    DIRECTION INPUT ;
    USE SIGNAL ;
    ANTENNAGATEAREA 0.180700 ;
    PORT
      LAYER Metal2 ;
        RECT 180.760 229.760 181.160 230.160 ;
    END
  END S4END[12]
  PIN S4END[13]
    DIRECTION INPUT ;
    USE SIGNAL ;
    ANTENNAGATEAREA 0.180700 ;
    PORT
      LAYER Metal2 ;
        RECT 182.680 229.760 183.080 230.160 ;
    END
  END S4END[13]
  PIN S4END[14]
    DIRECTION INPUT ;
    USE SIGNAL ;
    ANTENNAGATEAREA 0.180700 ;
    PORT
      LAYER Metal2 ;
        RECT 184.600 229.760 185.000 230.160 ;
    END
  END S4END[14]
  PIN S4END[15]
    DIRECTION INPUT ;
    USE SIGNAL ;
    ANTENNAGATEAREA 0.180700 ;
    PORT
      LAYER Metal2 ;
        RECT 186.520 229.760 186.920 230.160 ;
    END
  END S4END[15]
  PIN S4END[1]
    DIRECTION INPUT ;
    USE SIGNAL ;
    ANTENNAGATEAREA 1.918800 ;
    PORT
      LAYER Metal2 ;
        RECT 159.640 229.760 160.040 230.160 ;
    END
  END S4END[1]
  PIN S4END[2]
    DIRECTION INPUT ;
    USE SIGNAL ;
    ANTENNAGATEAREA 1.492400 ;
    PORT
      LAYER Metal2 ;
        RECT 161.560 229.760 161.960 230.160 ;
    END
  END S4END[2]
  PIN S4END[3]
    DIRECTION INPUT ;
    USE SIGNAL ;
    ANTENNAGATEAREA 1.492400 ;
    PORT
      LAYER Metal2 ;
        RECT 163.480 229.760 163.880 230.160 ;
    END
  END S4END[3]
  PIN S4END[4]
    DIRECTION INPUT ;
    USE SIGNAL ;
    ANTENNAGATEAREA 0.180700 ;
    PORT
      LAYER Metal2 ;
        RECT 165.400 229.760 165.800 230.160 ;
    END
  END S4END[4]
  PIN S4END[5]
    DIRECTION INPUT ;
    USE SIGNAL ;
    ANTENNAGATEAREA 0.180700 ;
    PORT
      LAYER Metal2 ;
        RECT 167.320 229.760 167.720 230.160 ;
    END
  END S4END[5]
  PIN S4END[6]
    DIRECTION INPUT ;
    USE SIGNAL ;
    ANTENNAGATEAREA 0.180700 ;
    PORT
      LAYER Metal2 ;
        RECT 169.240 229.760 169.640 230.160 ;
    END
  END S4END[6]
  PIN S4END[7]
    DIRECTION INPUT ;
    USE SIGNAL ;
    ANTENNAGATEAREA 0.180700 ;
    PORT
      LAYER Metal2 ;
        RECT 171.160 229.760 171.560 230.160 ;
    END
  END S4END[7]
  PIN S4END[8]
    DIRECTION INPUT ;
    USE SIGNAL ;
    ANTENNAGATEAREA 0.180700 ;
    PORT
      LAYER Metal2 ;
        RECT 173.080 229.760 173.480 230.160 ;
    END
  END S4END[8]
  PIN S4END[9]
    DIRECTION INPUT ;
    USE SIGNAL ;
    ANTENNAGATEAREA 0.180700 ;
    PORT
      LAYER Metal2 ;
        RECT 175.000 229.760 175.400 230.160 ;
    END
  END S4END[9]
  PIN SS4BEG[0]
    DIRECTION OUTPUT ;
    USE SIGNAL ;
    ANTENNADIFFAREA 2.724000 ;
    PORT
      LAYER Metal2 ;
        RECT 192.280 0.000 192.680 0.400 ;
    END
  END SS4BEG[0]
  PIN SS4BEG[10]
    DIRECTION OUTPUT ;
    USE SIGNAL ;
    ANTENNADIFFAREA 2.724000 ;
    PORT
      LAYER Metal2 ;
        RECT 211.480 0.000 211.880 0.400 ;
    END
  END SS4BEG[10]
  PIN SS4BEG[11]
    DIRECTION OUTPUT ;
    USE SIGNAL ;
    ANTENNADIFFAREA 2.724000 ;
    PORT
      LAYER Metal2 ;
        RECT 213.400 0.000 213.800 0.400 ;
    END
  END SS4BEG[11]
  PIN SS4BEG[12]
    DIRECTION OUTPUT ;
    USE SIGNAL ;
    ANTENNADIFFAREA 2.724000 ;
    PORT
      LAYER Metal2 ;
        RECT 215.320 0.000 215.720 0.400 ;
    END
  END SS4BEG[12]
  PIN SS4BEG[13]
    DIRECTION OUTPUT ;
    USE SIGNAL ;
    ANTENNADIFFAREA 2.724000 ;
    PORT
      LAYER Metal2 ;
        RECT 217.240 0.000 217.640 0.400 ;
    END
  END SS4BEG[13]
  PIN SS4BEG[14]
    DIRECTION OUTPUT ;
    USE SIGNAL ;
    ANTENNADIFFAREA 2.724000 ;
    PORT
      LAYER Metal2 ;
        RECT 219.160 0.000 219.560 0.400 ;
    END
  END SS4BEG[14]
  PIN SS4BEG[15]
    DIRECTION OUTPUT ;
    USE SIGNAL ;
    ANTENNADIFFAREA 2.724000 ;
    PORT
      LAYER Metal2 ;
        RECT 221.080 0.000 221.480 0.400 ;
    END
  END SS4BEG[15]
  PIN SS4BEG[1]
    DIRECTION OUTPUT ;
    USE SIGNAL ;
    ANTENNADIFFAREA 2.724000 ;
    PORT
      LAYER Metal2 ;
        RECT 194.200 0.000 194.600 0.400 ;
    END
  END SS4BEG[1]
  PIN SS4BEG[2]
    DIRECTION OUTPUT ;
    USE SIGNAL ;
    ANTENNADIFFAREA 2.724000 ;
    PORT
      LAYER Metal2 ;
        RECT 196.120 0.000 196.520 0.400 ;
    END
  END SS4BEG[2]
  PIN SS4BEG[3]
    DIRECTION OUTPUT ;
    USE SIGNAL ;
    ANTENNADIFFAREA 2.724000 ;
    PORT
      LAYER Metal2 ;
        RECT 198.040 0.000 198.440 0.400 ;
    END
  END SS4BEG[3]
  PIN SS4BEG[4]
    DIRECTION OUTPUT ;
    USE SIGNAL ;
    ANTENNADIFFAREA 2.724000 ;
    PORT
      LAYER Metal2 ;
        RECT 199.960 0.000 200.360 0.400 ;
    END
  END SS4BEG[4]
  PIN SS4BEG[5]
    DIRECTION OUTPUT ;
    USE SIGNAL ;
    ANTENNADIFFAREA 2.724000 ;
    PORT
      LAYER Metal2 ;
        RECT 201.880 0.000 202.280 0.400 ;
    END
  END SS4BEG[5]
  PIN SS4BEG[6]
    DIRECTION OUTPUT ;
    USE SIGNAL ;
    ANTENNADIFFAREA 2.724000 ;
    PORT
      LAYER Metal2 ;
        RECT 203.800 0.000 204.200 0.400 ;
    END
  END SS4BEG[6]
  PIN SS4BEG[7]
    DIRECTION OUTPUT ;
    USE SIGNAL ;
    ANTENNADIFFAREA 2.724000 ;
    PORT
      LAYER Metal2 ;
        RECT 205.720 0.000 206.120 0.400 ;
    END
  END SS4BEG[7]
  PIN SS4BEG[8]
    DIRECTION OUTPUT ;
    USE SIGNAL ;
    ANTENNADIFFAREA 2.724000 ;
    PORT
      LAYER Metal2 ;
        RECT 207.640 0.000 208.040 0.400 ;
    END
  END SS4BEG[8]
  PIN SS4BEG[9]
    DIRECTION OUTPUT ;
    USE SIGNAL ;
    ANTENNADIFFAREA 2.724000 ;
    PORT
      LAYER Metal2 ;
        RECT 209.560 0.000 209.960 0.400 ;
    END
  END SS4BEG[9]
  PIN SS4END[0]
    DIRECTION INPUT ;
    USE SIGNAL ;
    ANTENNAGATEAREA 1.505400 ;
    PORT
      LAYER Metal2 ;
        RECT 192.280 229.760 192.680 230.160 ;
    END
  END SS4END[0]
  PIN SS4END[10]
    DIRECTION INPUT ;
    USE SIGNAL ;
    ANTENNAGATEAREA 0.180700 ;
    PORT
      LAYER Metal2 ;
        RECT 211.480 229.760 211.880 230.160 ;
    END
  END SS4END[10]
  PIN SS4END[11]
    DIRECTION INPUT ;
    USE SIGNAL ;
    ANTENNAGATEAREA 0.180700 ;
    PORT
      LAYER Metal2 ;
        RECT 213.400 229.760 213.800 230.160 ;
    END
  END SS4END[11]
  PIN SS4END[12]
    DIRECTION INPUT ;
    USE SIGNAL ;
    ANTENNAGATEAREA 0.180700 ;
    PORT
      LAYER Metal2 ;
        RECT 215.320 229.760 215.720 230.160 ;
    END
  END SS4END[12]
  PIN SS4END[13]
    DIRECTION INPUT ;
    USE SIGNAL ;
    ANTENNAGATEAREA 0.180700 ;
    PORT
      LAYER Metal2 ;
        RECT 217.240 229.760 217.640 230.160 ;
    END
  END SS4END[13]
  PIN SS4END[14]
    DIRECTION INPUT ;
    USE SIGNAL ;
    ANTENNAGATEAREA 0.180700 ;
    PORT
      LAYER Metal2 ;
        RECT 219.160 229.760 219.560 230.160 ;
    END
  END SS4END[14]
  PIN SS4END[15]
    DIRECTION INPUT ;
    USE SIGNAL ;
    ANTENNAGATEAREA 0.180700 ;
    PORT
      LAYER Metal2 ;
        RECT 221.080 229.760 221.480 230.160 ;
    END
  END SS4END[15]
  PIN SS4END[1]
    DIRECTION INPUT ;
    USE SIGNAL ;
    ANTENNAGATEAREA 1.918800 ;
    PORT
      LAYER Metal2 ;
        RECT 194.200 229.760 194.600 230.160 ;
    END
  END SS4END[1]
  PIN SS4END[2]
    DIRECTION INPUT ;
    USE SIGNAL ;
    ANTENNAGATEAREA 1.705600 ;
    PORT
      LAYER Metal2 ;
        RECT 196.120 229.760 196.520 230.160 ;
    END
  END SS4END[2]
  PIN SS4END[3]
    DIRECTION INPUT ;
    USE SIGNAL ;
    ANTENNAGATEAREA 1.492400 ;
    PORT
      LAYER Metal2 ;
        RECT 198.040 229.760 198.440 230.160 ;
    END
  END SS4END[3]
  PIN SS4END[4]
    DIRECTION INPUT ;
    USE SIGNAL ;
    ANTENNAGATEAREA 0.180700 ;
    PORT
      LAYER Metal2 ;
        RECT 199.960 229.760 200.360 230.160 ;
    END
  END SS4END[4]
  PIN SS4END[5]
    DIRECTION INPUT ;
    USE SIGNAL ;
    ANTENNAGATEAREA 0.180700 ;
    PORT
      LAYER Metal2 ;
        RECT 201.880 229.760 202.280 230.160 ;
    END
  END SS4END[5]
  PIN SS4END[6]
    DIRECTION INPUT ;
    USE SIGNAL ;
    ANTENNAGATEAREA 0.180700 ;
    PORT
      LAYER Metal2 ;
        RECT 203.800 229.760 204.200 230.160 ;
    END
  END SS4END[6]
  PIN SS4END[7]
    DIRECTION INPUT ;
    USE SIGNAL ;
    ANTENNAGATEAREA 0.180700 ;
    PORT
      LAYER Metal2 ;
        RECT 205.720 229.760 206.120 230.160 ;
    END
  END SS4END[7]
  PIN SS4END[8]
    DIRECTION INPUT ;
    USE SIGNAL ;
    ANTENNAGATEAREA 0.180700 ;
    PORT
      LAYER Metal2 ;
        RECT 207.640 229.760 208.040 230.160 ;
    END
  END SS4END[8]
  PIN SS4END[9]
    DIRECTION INPUT ;
    USE SIGNAL ;
    ANTENNAGATEAREA 0.180700 ;
    PORT
      LAYER Metal2 ;
        RECT 209.560 229.760 209.960 230.160 ;
    END
  END SS4END[9]
  PIN UserCLK
    DIRECTION INPUT ;
    USE SIGNAL ;
    ANTENNAGATEAREA 1.450800 ;
    PORT
      LAYER Metal3 ;
        RECT 0.000 171.580 0.400 171.980 ;
    END
  END UserCLK
  PIN UserCLKo
    DIRECTION OUTPUT ;
    USE SIGNAL ;
    ANTENNADIFFAREA 2.724000 ;
    PORT
      LAYER Metal3 ;
        RECT 269.840 171.580 270.240 171.980 ;
    END
  END UserCLKo
  PIN VGND
    DIRECTION INOUT ;
    USE GROUND ;
    PORT
      LAYER Metal4 ;
        RECT 13.940 0.000 14.940 230.160 ;
    END
    PORT
      LAYER Metal4 ;
        RECT 63.940 0.000 64.940 230.160 ;
    END
    PORT
      LAYER Metal4 ;
        RECT 113.940 0.000 114.940 230.160 ;
    END
    PORT
      LAYER Metal4 ;
        RECT 163.940 0.000 164.940 230.160 ;
    END
    PORT
      LAYER Metal4 ;
        RECT 213.940 0.000 214.940 230.160 ;
    END
    PORT
      LAYER Metal4 ;
        RECT 263.940 0.000 264.940 230.160 ;
    END
  END VGND
  PIN VPWR
    DIRECTION INOUT ;
    USE POWER ;
    PORT
      LAYER Metal4 ;
        RECT 10.940 0.000 11.940 230.160 ;
    END
    PORT
      LAYER Metal4 ;
        RECT 60.940 0.000 61.940 230.160 ;
    END
    PORT
      LAYER Metal4 ;
        RECT 110.940 0.000 111.940 230.160 ;
    END
    PORT
      LAYER Metal4 ;
        RECT 160.940 0.000 161.940 230.160 ;
    END
    PORT
      LAYER Metal4 ;
        RECT 210.940 0.000 211.940 230.160 ;
    END
    PORT
      LAYER Metal4 ;
        RECT 260.940 0.000 261.940 230.160 ;
    END
  END VPWR
  PIN W1BEG[0]
    DIRECTION OUTPUT ;
    USE SIGNAL ;
    ANTENNADIFFAREA 2.724000 ;
    PORT
      LAYER Metal3 ;
        RECT 0.000 85.900 0.400 86.300 ;
    END
  END W1BEG[0]
  PIN W1BEG[1]
    DIRECTION OUTPUT ;
    USE SIGNAL ;
    ANTENNADIFFAREA 2.724000 ;
    PORT
      LAYER Metal3 ;
        RECT 0.000 87.580 0.400 87.980 ;
    END
  END W1BEG[1]
  PIN W1BEG[2]
    DIRECTION OUTPUT ;
    USE SIGNAL ;
    ANTENNADIFFAREA 2.724000 ;
    PORT
      LAYER Metal3 ;
        RECT 0.000 89.260 0.400 89.660 ;
    END
  END W1BEG[2]
  PIN W1BEG[3]
    DIRECTION OUTPUT ;
    USE SIGNAL ;
    ANTENNADIFFAREA 2.724000 ;
    PORT
      LAYER Metal3 ;
        RECT 0.000 90.940 0.400 91.340 ;
    END
  END W1BEG[3]
  PIN W1END[0]
    DIRECTION INPUT ;
    USE SIGNAL ;
    ANTENNAGATEAREA 2.345200 ;
    PORT
      LAYER Metal3 ;
        RECT 269.840 85.900 270.240 86.300 ;
    END
  END W1END[0]
  PIN W1END[1]
    DIRECTION INPUT ;
    USE SIGNAL ;
    ANTENNAGATEAREA 1.918800 ;
    PORT
      LAYER Metal3 ;
        RECT 269.840 87.580 270.240 87.980 ;
    END
  END W1END[1]
  PIN W1END[2]
    DIRECTION INPUT ;
    USE SIGNAL ;
    ANTENNAGATEAREA 2.132000 ;
    PORT
      LAYER Metal3 ;
        RECT 269.840 89.260 270.240 89.660 ;
    END
  END W1END[2]
  PIN W1END[3]
    DIRECTION INPUT ;
    USE SIGNAL ;
    ANTENNAGATEAREA 1.066000 ;
    ANTENNADIFFAREA 40.307999 ;
    PORT
      LAYER Metal3 ;
        RECT 269.840 90.940 270.240 91.340 ;
    END
  END W1END[3]
  PIN W2BEG[0]
    DIRECTION OUTPUT ;
    USE SIGNAL ;
    ANTENNADIFFAREA 2.724000 ;
    PORT
      LAYER Metal3 ;
        RECT 0.000 93.460 0.400 93.860 ;
    END
  END W2BEG[0]
  PIN W2BEG[1]
    DIRECTION OUTPUT ;
    USE SIGNAL ;
    ANTENNADIFFAREA 2.724000 ;
    PORT
      LAYER Metal3 ;
        RECT 0.000 95.140 0.400 95.540 ;
    END
  END W2BEG[1]
  PIN W2BEG[2]
    DIRECTION OUTPUT ;
    USE SIGNAL ;
    ANTENNADIFFAREA 2.724000 ;
    PORT
      LAYER Metal3 ;
        RECT 0.000 96.820 0.400 97.220 ;
    END
  END W2BEG[2]
  PIN W2BEG[3]
    DIRECTION OUTPUT ;
    USE SIGNAL ;
    ANTENNADIFFAREA 2.724000 ;
    PORT
      LAYER Metal3 ;
        RECT 0.000 98.500 0.400 98.900 ;
    END
  END W2BEG[3]
  PIN W2BEG[4]
    DIRECTION OUTPUT ;
    USE SIGNAL ;
    ANTENNADIFFAREA 2.724000 ;
    PORT
      LAYER Metal3 ;
        RECT 0.000 100.180 0.400 100.580 ;
    END
  END W2BEG[4]
  PIN W2BEG[5]
    DIRECTION OUTPUT ;
    USE SIGNAL ;
    ANTENNADIFFAREA 2.724000 ;
    PORT
      LAYER Metal3 ;
        RECT 0.000 101.860 0.400 102.260 ;
    END
  END W2BEG[5]
  PIN W2BEG[6]
    DIRECTION OUTPUT ;
    USE SIGNAL ;
    ANTENNADIFFAREA 2.724000 ;
    PORT
      LAYER Metal3 ;
        RECT 0.000 103.540 0.400 103.940 ;
    END
  END W2BEG[6]
  PIN W2BEG[7]
    DIRECTION OUTPUT ;
    USE SIGNAL ;
    ANTENNADIFFAREA 2.724000 ;
    PORT
      LAYER Metal3 ;
        RECT 0.000 105.220 0.400 105.620 ;
    END
  END W2BEG[7]
  PIN W2BEGb[0]
    DIRECTION OUTPUT ;
    USE SIGNAL ;
    ANTENNADIFFAREA 2.724000 ;
    PORT
      LAYER Metal3 ;
        RECT 0.000 107.740 0.400 108.140 ;
    END
  END W2BEGb[0]
  PIN W2BEGb[1]
    DIRECTION OUTPUT ;
    USE SIGNAL ;
    ANTENNADIFFAREA 2.724000 ;
    PORT
      LAYER Metal3 ;
        RECT 0.000 109.420 0.400 109.820 ;
    END
  END W2BEGb[1]
  PIN W2BEGb[2]
    DIRECTION OUTPUT ;
    USE SIGNAL ;
    ANTENNADIFFAREA 2.724000 ;
    PORT
      LAYER Metal3 ;
        RECT 0.000 111.100 0.400 111.500 ;
    END
  END W2BEGb[2]
  PIN W2BEGb[3]
    DIRECTION OUTPUT ;
    USE SIGNAL ;
    ANTENNADIFFAREA 2.724000 ;
    PORT
      LAYER Metal3 ;
        RECT 0.000 112.780 0.400 113.180 ;
    END
  END W2BEGb[3]
  PIN W2BEGb[4]
    DIRECTION OUTPUT ;
    USE SIGNAL ;
    ANTENNADIFFAREA 2.724000 ;
    PORT
      LAYER Metal3 ;
        RECT 0.000 114.460 0.400 114.860 ;
    END
  END W2BEGb[4]
  PIN W2BEGb[5]
    DIRECTION OUTPUT ;
    USE SIGNAL ;
    ANTENNADIFFAREA 2.724000 ;
    PORT
      LAYER Metal3 ;
        RECT 0.000 116.140 0.400 116.540 ;
    END
  END W2BEGb[5]
  PIN W2BEGb[6]
    DIRECTION OUTPUT ;
    USE SIGNAL ;
    ANTENNADIFFAREA 2.724000 ;
    PORT
      LAYER Metal3 ;
        RECT 0.000 117.820 0.400 118.220 ;
    END
  END W2BEGb[6]
  PIN W2BEGb[7]
    DIRECTION OUTPUT ;
    USE SIGNAL ;
    ANTENNADIFFAREA 2.724000 ;
    PORT
      LAYER Metal3 ;
        RECT 0.000 119.500 0.400 119.900 ;
    END
  END W2BEGb[7]
  PIN W2END[0]
    DIRECTION INPUT ;
    USE SIGNAL ;
    ANTENNAGATEAREA 1.305200 ;
    PORT
      LAYER Metal3 ;
        RECT 269.840 107.740 270.240 108.140 ;
    END
  END W2END[0]
  PIN W2END[1]
    DIRECTION INPUT ;
    USE SIGNAL ;
    ANTENNAGATEAREA 0.852800 ;
    ANTENNADIFFAREA 8.061600 ;
    PORT
      LAYER Metal3 ;
        RECT 269.840 109.420 270.240 109.820 ;
    END
  END W2END[1]
  PIN W2END[2]
    DIRECTION INPUT ;
    USE SIGNAL ;
    ANTENNAGATEAREA 1.279200 ;
    ANTENNADIFFAREA 14.107800 ;
    PORT
      LAYER Metal3 ;
        RECT 269.840 111.100 270.240 111.500 ;
    END
  END W2END[2]
  PIN W2END[3]
    DIRECTION INPUT ;
    USE SIGNAL ;
    ANTENNAGATEAREA 1.705600 ;
    PORT
      LAYER Metal3 ;
        RECT 269.840 112.780 270.240 113.180 ;
    END
  END W2END[3]
  PIN W2END[4]
    DIRECTION INPUT ;
    USE SIGNAL ;
    ANTENNAGATEAREA 1.705600 ;
    PORT
      LAYER Metal3 ;
        RECT 269.840 114.460 270.240 114.860 ;
    END
  END W2END[4]
  PIN W2END[5]
    DIRECTION INPUT ;
    USE SIGNAL ;
    ANTENNAGATEAREA 1.492400 ;
    PORT
      LAYER Metal3 ;
        RECT 269.840 116.140 270.240 116.540 ;
    END
  END W2END[5]
  PIN W2END[6]
    DIRECTION INPUT ;
    USE SIGNAL ;
    ANTENNAGATEAREA 1.505400 ;
    PORT
      LAYER Metal3 ;
        RECT 269.840 117.820 270.240 118.220 ;
    END
  END W2END[6]
  PIN W2END[7]
    DIRECTION INPUT ;
    USE SIGNAL ;
    ANTENNAGATEAREA 0.852800 ;
    ANTENNADIFFAREA 8.061600 ;
    PORT
      LAYER Metal3 ;
        RECT 269.840 119.500 270.240 119.900 ;
    END
  END W2END[7]
  PIN W2MID[0]
    DIRECTION INPUT ;
    USE SIGNAL ;
    ANTENNAGATEAREA 1.459900 ;
    PORT
      LAYER Metal3 ;
        RECT 269.840 93.460 270.240 93.860 ;
    END
  END W2MID[0]
  PIN W2MID[1]
    DIRECTION INPUT ;
    USE SIGNAL ;
    ANTENNAGATEAREA 1.673100 ;
    PORT
      LAYER Metal3 ;
        RECT 269.840 95.140 270.240 95.540 ;
    END
  END W2MID[1]
  PIN W2MID[2]
    DIRECTION INPUT ;
    USE SIGNAL ;
    ANTENNAGATEAREA 1.459900 ;
    PORT
      LAYER Metal3 ;
        RECT 269.840 96.820 270.240 97.220 ;
    END
  END W2MID[2]
  PIN W2MID[3]
    DIRECTION INPUT ;
    USE SIGNAL ;
    ANTENNAGATEAREA 1.459900 ;
    PORT
      LAYER Metal3 ;
        RECT 269.840 98.500 270.240 98.900 ;
    END
  END W2MID[3]
  PIN W2MID[4]
    DIRECTION INPUT ;
    USE SIGNAL ;
    ANTENNAGATEAREA 1.673100 ;
    PORT
      LAYER Metal3 ;
        RECT 269.840 100.180 270.240 100.580 ;
    END
  END W2MID[4]
  PIN W2MID[5]
    DIRECTION INPUT ;
    USE SIGNAL ;
    ANTENNAGATEAREA 1.886300 ;
    PORT
      LAYER Metal3 ;
        RECT 269.840 101.860 270.240 102.260 ;
    END
  END W2MID[5]
  PIN W2MID[6]
    DIRECTION INPUT ;
    USE SIGNAL ;
    ANTENNAGATEAREA 1.459900 ;
    ANTENNADIFFAREA 28.215599 ;
    PORT
      LAYER Metal3 ;
        RECT 269.840 103.540 270.240 103.940 ;
    END
  END W2MID[6]
  PIN W2MID[7]
    DIRECTION INPUT ;
    USE SIGNAL ;
    ANTENNAGATEAREA 2.099500 ;
    PORT
      LAYER Metal3 ;
        RECT 269.840 105.220 270.240 105.620 ;
    END
  END W2MID[7]
  PIN W6BEG[0]
    DIRECTION OUTPUT ;
    USE SIGNAL ;
    ANTENNADIFFAREA 2.724000 ;
    PORT
      LAYER Metal3 ;
        RECT 0.000 150.580 0.400 150.980 ;
    END
  END W6BEG[0]
  PIN W6BEG[10]
    DIRECTION OUTPUT ;
    USE SIGNAL ;
    ANTENNADIFFAREA 2.724000 ;
    PORT
      LAYER Metal3 ;
        RECT 0.000 167.380 0.400 167.780 ;
    END
  END W6BEG[10]
  PIN W6BEG[11]
    DIRECTION OUTPUT ;
    USE SIGNAL ;
    ANTENNADIFFAREA 2.724000 ;
    PORT
      LAYER Metal3 ;
        RECT 0.000 169.060 0.400 169.460 ;
    END
  END W6BEG[11]
  PIN W6BEG[1]
    DIRECTION OUTPUT ;
    USE SIGNAL ;
    ANTENNADIFFAREA 2.724000 ;
    PORT
      LAYER Metal3 ;
        RECT 0.000 152.260 0.400 152.660 ;
    END
  END W6BEG[1]
  PIN W6BEG[2]
    DIRECTION OUTPUT ;
    USE SIGNAL ;
    ANTENNADIFFAREA 2.724000 ;
    PORT
      LAYER Metal3 ;
        RECT 0.000 153.940 0.400 154.340 ;
    END
  END W6BEG[2]
  PIN W6BEG[3]
    DIRECTION OUTPUT ;
    USE SIGNAL ;
    ANTENNADIFFAREA 2.724000 ;
    PORT
      LAYER Metal3 ;
        RECT 0.000 155.620 0.400 156.020 ;
    END
  END W6BEG[3]
  PIN W6BEG[4]
    DIRECTION OUTPUT ;
    USE SIGNAL ;
    ANTENNADIFFAREA 2.724000 ;
    PORT
      LAYER Metal3 ;
        RECT 0.000 157.300 0.400 157.700 ;
    END
  END W6BEG[4]
  PIN W6BEG[5]
    DIRECTION OUTPUT ;
    USE SIGNAL ;
    ANTENNADIFFAREA 2.724000 ;
    PORT
      LAYER Metal3 ;
        RECT 0.000 158.980 0.400 159.380 ;
    END
  END W6BEG[5]
  PIN W6BEG[6]
    DIRECTION OUTPUT ;
    USE SIGNAL ;
    ANTENNADIFFAREA 2.724000 ;
    PORT
      LAYER Metal3 ;
        RECT 0.000 160.660 0.400 161.060 ;
    END
  END W6BEG[6]
  PIN W6BEG[7]
    DIRECTION OUTPUT ;
    USE SIGNAL ;
    ANTENNADIFFAREA 2.724000 ;
    PORT
      LAYER Metal3 ;
        RECT 0.000 162.340 0.400 162.740 ;
    END
  END W6BEG[7]
  PIN W6BEG[8]
    DIRECTION OUTPUT ;
    USE SIGNAL ;
    ANTENNADIFFAREA 2.724000 ;
    PORT
      LAYER Metal3 ;
        RECT 0.000 164.020 0.400 164.420 ;
    END
  END W6BEG[8]
  PIN W6BEG[9]
    DIRECTION OUTPUT ;
    USE SIGNAL ;
    ANTENNADIFFAREA 2.724000 ;
    PORT
      LAYER Metal3 ;
        RECT 0.000 165.700 0.400 166.100 ;
    END
  END W6BEG[9]
  PIN W6END[0]
    DIRECTION INPUT ;
    USE SIGNAL ;
    ANTENNAGATEAREA 1.718600 ;
    PORT
      LAYER Metal3 ;
        RECT 269.840 150.580 270.240 150.980 ;
    END
  END W6END[0]
  PIN W6END[10]
    DIRECTION INPUT ;
    USE SIGNAL ;
    ANTENNAGATEAREA 0.180700 ;
    PORT
      LAYER Metal3 ;
        RECT 269.840 167.380 270.240 167.780 ;
    END
  END W6END[10]
  PIN W6END[11]
    DIRECTION INPUT ;
    USE SIGNAL ;
    ANTENNAGATEAREA 0.180700 ;
    PORT
      LAYER Metal3 ;
        RECT 269.840 169.060 270.240 169.460 ;
    END
  END W6END[11]
  PIN W6END[1]
    DIRECTION INPUT ;
    USE SIGNAL ;
    ANTENNAGATEAREA 2.145000 ;
    PORT
      LAYER Metal3 ;
        RECT 269.840 152.260 270.240 152.660 ;
    END
  END W6END[1]
  PIN W6END[2]
    DIRECTION INPUT ;
    USE SIGNAL ;
    ANTENNAGATEAREA 0.180700 ;
    PORT
      LAYER Metal3 ;
        RECT 269.840 153.940 270.240 154.340 ;
    END
  END W6END[2]
  PIN W6END[3]
    DIRECTION INPUT ;
    USE SIGNAL ;
    ANTENNAGATEAREA 0.180700 ;
    PORT
      LAYER Metal3 ;
        RECT 269.840 155.620 270.240 156.020 ;
    END
  END W6END[3]
  PIN W6END[4]
    DIRECTION INPUT ;
    USE SIGNAL ;
    ANTENNAGATEAREA 0.180700 ;
    PORT
      LAYER Metal3 ;
        RECT 269.840 157.300 270.240 157.700 ;
    END
  END W6END[4]
  PIN W6END[5]
    DIRECTION INPUT ;
    USE SIGNAL ;
    ANTENNAGATEAREA 0.180700 ;
    PORT
      LAYER Metal3 ;
        RECT 269.840 158.980 270.240 159.380 ;
    END
  END W6END[5]
  PIN W6END[6]
    DIRECTION INPUT ;
    USE SIGNAL ;
    ANTENNAGATEAREA 0.180700 ;
    PORT
      LAYER Metal3 ;
        RECT 269.840 160.660 270.240 161.060 ;
    END
  END W6END[6]
  PIN W6END[7]
    DIRECTION INPUT ;
    USE SIGNAL ;
    ANTENNAGATEAREA 0.180700 ;
    PORT
      LAYER Metal3 ;
        RECT 269.840 162.340 270.240 162.740 ;
    END
  END W6END[7]
  PIN W6END[8]
    DIRECTION INPUT ;
    USE SIGNAL ;
    ANTENNAGATEAREA 0.180700 ;
    PORT
      LAYER Metal3 ;
        RECT 269.840 164.020 270.240 164.420 ;
    END
  END W6END[8]
  PIN W6END[9]
    DIRECTION INPUT ;
    USE SIGNAL ;
    ANTENNAGATEAREA 0.180700 ;
    PORT
      LAYER Metal3 ;
        RECT 269.840 165.700 270.240 166.100 ;
    END
  END W6END[9]
  PIN WW4BEG[0]
    DIRECTION OUTPUT ;
    USE SIGNAL ;
    ANTENNADIFFAREA 2.724000 ;
    PORT
      LAYER Metal3 ;
        RECT 0.000 122.020 0.400 122.420 ;
    END
  END WW4BEG[0]
  PIN WW4BEG[10]
    DIRECTION OUTPUT ;
    USE SIGNAL ;
    ANTENNADIFFAREA 2.724000 ;
    PORT
      LAYER Metal3 ;
        RECT 0.000 138.820 0.400 139.220 ;
    END
  END WW4BEG[10]
  PIN WW4BEG[11]
    DIRECTION OUTPUT ;
    USE SIGNAL ;
    ANTENNADIFFAREA 2.724000 ;
    PORT
      LAYER Metal3 ;
        RECT 0.000 140.500 0.400 140.900 ;
    END
  END WW4BEG[11]
  PIN WW4BEG[12]
    DIRECTION OUTPUT ;
    USE SIGNAL ;
    ANTENNADIFFAREA 2.724000 ;
    PORT
      LAYER Metal3 ;
        RECT 0.000 142.180 0.400 142.580 ;
    END
  END WW4BEG[12]
  PIN WW4BEG[13]
    DIRECTION OUTPUT ;
    USE SIGNAL ;
    ANTENNADIFFAREA 2.724000 ;
    PORT
      LAYER Metal3 ;
        RECT 0.000 143.860 0.400 144.260 ;
    END
  END WW4BEG[13]
  PIN WW4BEG[14]
    DIRECTION OUTPUT ;
    USE SIGNAL ;
    ANTENNADIFFAREA 2.724000 ;
    PORT
      LAYER Metal3 ;
        RECT 0.000 145.540 0.400 145.940 ;
    END
  END WW4BEG[14]
  PIN WW4BEG[15]
    DIRECTION OUTPUT ;
    USE SIGNAL ;
    ANTENNADIFFAREA 2.724000 ;
    PORT
      LAYER Metal3 ;
        RECT 0.000 147.220 0.400 147.620 ;
    END
  END WW4BEG[15]
  PIN WW4BEG[1]
    DIRECTION OUTPUT ;
    USE SIGNAL ;
    ANTENNADIFFAREA 2.724000 ;
    PORT
      LAYER Metal3 ;
        RECT 0.000 123.700 0.400 124.100 ;
    END
  END WW4BEG[1]
  PIN WW4BEG[2]
    DIRECTION OUTPUT ;
    USE SIGNAL ;
    ANTENNADIFFAREA 2.724000 ;
    PORT
      LAYER Metal3 ;
        RECT 0.000 125.380 0.400 125.780 ;
    END
  END WW4BEG[2]
  PIN WW4BEG[3]
    DIRECTION OUTPUT ;
    USE SIGNAL ;
    ANTENNADIFFAREA 2.724000 ;
    PORT
      LAYER Metal3 ;
        RECT 0.000 127.060 0.400 127.460 ;
    END
  END WW4BEG[3]
  PIN WW4BEG[4]
    DIRECTION OUTPUT ;
    USE SIGNAL ;
    ANTENNADIFFAREA 2.724000 ;
    PORT
      LAYER Metal3 ;
        RECT 0.000 128.740 0.400 129.140 ;
    END
  END WW4BEG[4]
  PIN WW4BEG[5]
    DIRECTION OUTPUT ;
    USE SIGNAL ;
    ANTENNADIFFAREA 2.724000 ;
    PORT
      LAYER Metal3 ;
        RECT 0.000 130.420 0.400 130.820 ;
    END
  END WW4BEG[5]
  PIN WW4BEG[6]
    DIRECTION OUTPUT ;
    USE SIGNAL ;
    ANTENNADIFFAREA 2.724000 ;
    PORT
      LAYER Metal3 ;
        RECT 0.000 132.100 0.400 132.500 ;
    END
  END WW4BEG[6]
  PIN WW4BEG[7]
    DIRECTION OUTPUT ;
    USE SIGNAL ;
    ANTENNADIFFAREA 2.724000 ;
    PORT
      LAYER Metal3 ;
        RECT 0.000 133.780 0.400 134.180 ;
    END
  END WW4BEG[7]
  PIN WW4BEG[8]
    DIRECTION OUTPUT ;
    USE SIGNAL ;
    ANTENNADIFFAREA 2.724000 ;
    PORT
      LAYER Metal3 ;
        RECT 0.000 135.460 0.400 135.860 ;
    END
  END WW4BEG[8]
  PIN WW4BEG[9]
    DIRECTION OUTPUT ;
    USE SIGNAL ;
    ANTENNADIFFAREA 2.724000 ;
    PORT
      LAYER Metal3 ;
        RECT 0.000 137.140 0.400 137.540 ;
    END
  END WW4BEG[9]
  PIN WW4END[0]
    DIRECTION INPUT ;
    USE SIGNAL ;
    ANTENNAGATEAREA 1.734200 ;
    ANTENNADIFFAREA 32.246399 ;
    PORT
      LAYER Metal3 ;
        RECT 269.840 122.020 270.240 122.420 ;
    END
  END WW4END[0]
  PIN WW4END[10]
    DIRECTION INPUT ;
    USE SIGNAL ;
    ANTENNAGATEAREA 0.180700 ;
    PORT
      LAYER Metal3 ;
        RECT 269.840 138.820 270.240 139.220 ;
    END
  END WW4END[10]
  PIN WW4END[11]
    DIRECTION INPUT ;
    USE SIGNAL ;
    ANTENNAGATEAREA 0.180700 ;
    PORT
      LAYER Metal3 ;
        RECT 269.840 140.500 270.240 140.900 ;
    END
  END WW4END[11]
  PIN WW4END[12]
    DIRECTION INPUT ;
    USE SIGNAL ;
    ANTENNAGATEAREA 0.180700 ;
    PORT
      LAYER Metal3 ;
        RECT 269.840 142.180 270.240 142.580 ;
    END
  END WW4END[12]
  PIN WW4END[13]
    DIRECTION INPUT ;
    USE SIGNAL ;
    ANTENNAGATEAREA 0.180700 ;
    PORT
      LAYER Metal3 ;
        RECT 269.840 143.860 270.240 144.260 ;
    END
  END WW4END[13]
  PIN WW4END[14]
    DIRECTION INPUT ;
    USE SIGNAL ;
    ANTENNAGATEAREA 0.180700 ;
    PORT
      LAYER Metal3 ;
        RECT 269.840 145.540 270.240 145.940 ;
    END
  END WW4END[14]
  PIN WW4END[15]
    DIRECTION INPUT ;
    USE SIGNAL ;
    ANTENNAGATEAREA 0.180700 ;
    PORT
      LAYER Metal3 ;
        RECT 269.840 147.220 270.240 147.620 ;
    END
  END WW4END[15]
  PIN WW4END[1]
    DIRECTION INPUT ;
    USE SIGNAL ;
    ANTENNAGATEAREA 1.705600 ;
    PORT
      LAYER Metal3 ;
        RECT 269.840 123.700 270.240 124.100 ;
    END
  END WW4END[1]
  PIN WW4END[2]
    DIRECTION INPUT ;
    USE SIGNAL ;
    ANTENNAGATEAREA 1.705600 ;
    PORT
      LAYER Metal3 ;
        RECT 269.840 125.380 270.240 125.780 ;
    END
  END WW4END[2]
  PIN WW4END[3]
    DIRECTION INPUT ;
    USE SIGNAL ;
    ANTENNAGATEAREA 1.279200 ;
    ANTENNADIFFAREA 16.123199 ;
    PORT
      LAYER Metal3 ;
        RECT 269.840 127.060 270.240 127.460 ;
    END
  END WW4END[3]
  PIN WW4END[4]
    DIRECTION INPUT ;
    USE SIGNAL ;
    ANTENNAGATEAREA 0.180700 ;
    PORT
      LAYER Metal3 ;
        RECT 269.840 128.740 270.240 129.140 ;
    END
  END WW4END[4]
  PIN WW4END[5]
    DIRECTION INPUT ;
    USE SIGNAL ;
    ANTENNAGATEAREA 0.180700 ;
    PORT
      LAYER Metal3 ;
        RECT 269.840 130.420 270.240 130.820 ;
    END
  END WW4END[5]
  PIN WW4END[6]
    DIRECTION INPUT ;
    USE SIGNAL ;
    ANTENNAGATEAREA 0.180700 ;
    PORT
      LAYER Metal3 ;
        RECT 269.840 132.100 270.240 132.500 ;
    END
  END WW4END[6]
  PIN WW4END[7]
    DIRECTION INPUT ;
    USE SIGNAL ;
    ANTENNAGATEAREA 0.180700 ;
    PORT
      LAYER Metal3 ;
        RECT 269.840 133.780 270.240 134.180 ;
    END
  END WW4END[7]
  PIN WW4END[8]
    DIRECTION INPUT ;
    USE SIGNAL ;
    ANTENNAGATEAREA 0.180700 ;
    PORT
      LAYER Metal3 ;
        RECT 269.840 135.460 270.240 135.860 ;
    END
  END WW4END[8]
  PIN WW4END[9]
    DIRECTION INPUT ;
    USE SIGNAL ;
    ANTENNAGATEAREA 0.180700 ;
    PORT
      LAYER Metal3 ;
        RECT 269.840 137.140 270.240 137.540 ;
    END
  END WW4END[9]
  OBS
      LAYER GatPoly ;
        RECT 1.440 3.630 268.800 223.170 ;
      LAYER Metal1 ;
        RECT 1.440 3.560 268.800 223.240 ;
      LAYER Metal2 ;
        RECT 0.375 229.550 1.990 229.885 ;
        RECT 2.810 229.550 3.910 229.885 ;
        RECT 4.730 229.550 5.830 229.885 ;
        RECT 6.650 229.550 7.750 229.885 ;
        RECT 8.570 229.550 10.630 229.885 ;
        RECT 11.450 229.550 12.550 229.885 ;
        RECT 13.370 229.550 14.470 229.885 ;
        RECT 15.290 229.550 16.390 229.885 ;
        RECT 17.210 229.550 18.310 229.885 ;
        RECT 19.130 229.550 20.230 229.885 ;
        RECT 21.050 229.550 22.150 229.885 ;
        RECT 22.970 229.550 24.070 229.885 ;
        RECT 24.890 229.550 26.950 229.885 ;
        RECT 27.770 229.550 28.870 229.885 ;
        RECT 29.690 229.550 30.790 229.885 ;
        RECT 31.610 229.550 32.710 229.885 ;
        RECT 33.530 229.550 34.630 229.885 ;
        RECT 35.450 229.550 36.550 229.885 ;
        RECT 37.370 229.550 38.470 229.885 ;
        RECT 39.290 229.550 40.390 229.885 ;
        RECT 41.210 229.550 45.190 229.885 ;
        RECT 46.010 229.550 47.110 229.885 ;
        RECT 47.930 229.550 49.030 229.885 ;
        RECT 49.850 229.550 50.950 229.885 ;
        RECT 51.770 229.550 52.870 229.885 ;
        RECT 53.690 229.550 54.790 229.885 ;
        RECT 55.610 229.550 56.710 229.885 ;
        RECT 57.530 229.550 58.630 229.885 ;
        RECT 59.450 229.550 60.550 229.885 ;
        RECT 61.370 229.550 62.470 229.885 ;
        RECT 63.290 229.550 64.390 229.885 ;
        RECT 65.210 229.550 66.310 229.885 ;
        RECT 67.130 229.550 68.230 229.885 ;
        RECT 69.050 229.550 70.150 229.885 ;
        RECT 70.970 229.550 72.070 229.885 ;
        RECT 72.890 229.550 73.990 229.885 ;
        RECT 74.810 229.550 79.750 229.885 ;
        RECT 80.570 229.550 81.670 229.885 ;
        RECT 82.490 229.550 83.590 229.885 ;
        RECT 84.410 229.550 85.510 229.885 ;
        RECT 86.330 229.550 87.430 229.885 ;
        RECT 88.250 229.550 89.350 229.885 ;
        RECT 90.170 229.550 91.270 229.885 ;
        RECT 92.090 229.550 93.190 229.885 ;
        RECT 94.010 229.550 95.110 229.885 ;
        RECT 95.930 229.550 97.030 229.885 ;
        RECT 97.850 229.550 98.950 229.885 ;
        RECT 99.770 229.550 100.870 229.885 ;
        RECT 101.690 229.550 102.790 229.885 ;
        RECT 103.610 229.550 104.710 229.885 ;
        RECT 105.530 229.550 106.630 229.885 ;
        RECT 107.450 229.550 108.550 229.885 ;
        RECT 109.370 229.550 113.350 229.885 ;
        RECT 114.170 229.550 115.270 229.885 ;
        RECT 116.090 229.550 117.190 229.885 ;
        RECT 118.010 229.550 119.110 229.885 ;
        RECT 119.930 229.550 121.990 229.885 ;
        RECT 122.810 229.550 123.910 229.885 ;
        RECT 124.730 229.550 125.830 229.885 ;
        RECT 126.650 229.550 127.750 229.885 ;
        RECT 128.570 229.550 129.670 229.885 ;
        RECT 130.490 229.550 131.590 229.885 ;
        RECT 132.410 229.550 133.510 229.885 ;
        RECT 134.330 229.550 135.430 229.885 ;
        RECT 136.250 229.550 139.270 229.885 ;
        RECT 140.090 229.550 141.190 229.885 ;
        RECT 142.010 229.550 143.110 229.885 ;
        RECT 143.930 229.550 145.030 229.885 ;
        RECT 145.850 229.550 146.950 229.885 ;
        RECT 147.770 229.550 148.870 229.885 ;
        RECT 149.690 229.550 150.790 229.885 ;
        RECT 151.610 229.550 152.710 229.885 ;
        RECT 153.530 229.550 157.510 229.885 ;
        RECT 158.330 229.550 159.430 229.885 ;
        RECT 160.250 229.550 161.350 229.885 ;
        RECT 162.170 229.550 163.270 229.885 ;
        RECT 164.090 229.550 165.190 229.885 ;
        RECT 166.010 229.550 167.110 229.885 ;
        RECT 167.930 229.550 169.030 229.885 ;
        RECT 169.850 229.550 170.950 229.885 ;
        RECT 171.770 229.550 172.870 229.885 ;
        RECT 173.690 229.550 174.790 229.885 ;
        RECT 175.610 229.550 176.710 229.885 ;
        RECT 177.530 229.550 178.630 229.885 ;
        RECT 179.450 229.550 180.550 229.885 ;
        RECT 181.370 229.550 182.470 229.885 ;
        RECT 183.290 229.550 184.390 229.885 ;
        RECT 185.210 229.550 186.310 229.885 ;
        RECT 187.130 229.550 192.070 229.885 ;
        RECT 192.890 229.550 193.990 229.885 ;
        RECT 194.810 229.550 195.910 229.885 ;
        RECT 196.730 229.550 197.830 229.885 ;
        RECT 198.650 229.550 199.750 229.885 ;
        RECT 200.570 229.550 201.670 229.885 ;
        RECT 202.490 229.550 203.590 229.885 ;
        RECT 204.410 229.550 205.510 229.885 ;
        RECT 206.330 229.550 207.430 229.885 ;
        RECT 208.250 229.550 209.350 229.885 ;
        RECT 210.170 229.550 211.270 229.885 ;
        RECT 212.090 229.550 213.190 229.885 ;
        RECT 214.010 229.550 215.110 229.885 ;
        RECT 215.930 229.550 217.030 229.885 ;
        RECT 217.850 229.550 218.950 229.885 ;
        RECT 219.770 229.550 220.870 229.885 ;
        RECT 221.690 229.550 225.670 229.885 ;
        RECT 226.490 229.550 230.470 229.885 ;
        RECT 231.290 229.550 232.390 229.885 ;
        RECT 233.210 229.550 234.310 229.885 ;
        RECT 235.130 229.550 236.230 229.885 ;
        RECT 237.050 229.550 238.150 229.885 ;
        RECT 238.970 229.550 240.070 229.885 ;
        RECT 240.890 229.550 241.990 229.885 ;
        RECT 242.810 229.550 243.910 229.885 ;
        RECT 244.730 229.550 245.830 229.885 ;
        RECT 246.650 229.550 247.750 229.885 ;
        RECT 248.570 229.550 249.670 229.885 ;
        RECT 250.490 229.550 251.590 229.885 ;
        RECT 252.410 229.550 253.510 229.885 ;
        RECT 254.330 229.550 255.430 229.885 ;
        RECT 256.250 229.550 257.350 229.885 ;
        RECT 258.170 229.550 259.270 229.885 ;
        RECT 260.090 229.550 261.190 229.885 ;
        RECT 262.010 229.550 263.110 229.885 ;
        RECT 263.930 229.550 265.030 229.885 ;
        RECT 265.850 229.550 266.950 229.885 ;
        RECT 267.770 229.550 269.865 229.885 ;
        RECT 0.375 0.610 269.865 229.550 ;
        RECT 0.375 0.275 1.990 0.610 ;
        RECT 2.810 0.275 3.910 0.610 ;
        RECT 4.730 0.275 5.830 0.610 ;
        RECT 6.650 0.275 7.750 0.610 ;
        RECT 8.570 0.275 10.630 0.610 ;
        RECT 11.450 0.275 12.550 0.610 ;
        RECT 13.370 0.275 14.470 0.610 ;
        RECT 15.290 0.275 16.390 0.610 ;
        RECT 17.210 0.275 18.310 0.610 ;
        RECT 19.130 0.275 20.230 0.610 ;
        RECT 21.050 0.275 22.150 0.610 ;
        RECT 22.970 0.275 24.070 0.610 ;
        RECT 24.890 0.275 26.950 0.610 ;
        RECT 27.770 0.275 28.870 0.610 ;
        RECT 29.690 0.275 30.790 0.610 ;
        RECT 31.610 0.275 32.710 0.610 ;
        RECT 33.530 0.275 34.630 0.610 ;
        RECT 35.450 0.275 36.550 0.610 ;
        RECT 37.370 0.275 38.470 0.610 ;
        RECT 39.290 0.275 40.390 0.610 ;
        RECT 41.210 0.275 45.190 0.610 ;
        RECT 46.010 0.275 47.110 0.610 ;
        RECT 47.930 0.275 49.030 0.610 ;
        RECT 49.850 0.275 50.950 0.610 ;
        RECT 51.770 0.275 52.870 0.610 ;
        RECT 53.690 0.275 54.790 0.610 ;
        RECT 55.610 0.275 56.710 0.610 ;
        RECT 57.530 0.275 58.630 0.610 ;
        RECT 59.450 0.275 60.550 0.610 ;
        RECT 61.370 0.275 62.470 0.610 ;
        RECT 63.290 0.275 64.390 0.610 ;
        RECT 65.210 0.275 66.310 0.610 ;
        RECT 67.130 0.275 68.230 0.610 ;
        RECT 69.050 0.275 70.150 0.610 ;
        RECT 70.970 0.275 72.070 0.610 ;
        RECT 72.890 0.275 73.990 0.610 ;
        RECT 74.810 0.275 79.750 0.610 ;
        RECT 80.570 0.275 81.670 0.610 ;
        RECT 82.490 0.275 83.590 0.610 ;
        RECT 84.410 0.275 85.510 0.610 ;
        RECT 86.330 0.275 87.430 0.610 ;
        RECT 88.250 0.275 89.350 0.610 ;
        RECT 90.170 0.275 91.270 0.610 ;
        RECT 92.090 0.275 93.190 0.610 ;
        RECT 94.010 0.275 95.110 0.610 ;
        RECT 95.930 0.275 97.030 0.610 ;
        RECT 97.850 0.275 98.950 0.610 ;
        RECT 99.770 0.275 100.870 0.610 ;
        RECT 101.690 0.275 102.790 0.610 ;
        RECT 103.610 0.275 104.710 0.610 ;
        RECT 105.530 0.275 106.630 0.610 ;
        RECT 107.450 0.275 108.550 0.610 ;
        RECT 109.370 0.275 113.350 0.610 ;
        RECT 114.170 0.275 115.270 0.610 ;
        RECT 116.090 0.275 117.190 0.610 ;
        RECT 118.010 0.275 119.110 0.610 ;
        RECT 119.930 0.275 121.990 0.610 ;
        RECT 122.810 0.275 123.910 0.610 ;
        RECT 124.730 0.275 125.830 0.610 ;
        RECT 126.650 0.275 127.750 0.610 ;
        RECT 128.570 0.275 129.670 0.610 ;
        RECT 130.490 0.275 131.590 0.610 ;
        RECT 132.410 0.275 133.510 0.610 ;
        RECT 134.330 0.275 135.430 0.610 ;
        RECT 136.250 0.275 139.270 0.610 ;
        RECT 140.090 0.275 141.190 0.610 ;
        RECT 142.010 0.275 143.110 0.610 ;
        RECT 143.930 0.275 145.030 0.610 ;
        RECT 145.850 0.275 146.950 0.610 ;
        RECT 147.770 0.275 148.870 0.610 ;
        RECT 149.690 0.275 150.790 0.610 ;
        RECT 151.610 0.275 152.710 0.610 ;
        RECT 153.530 0.275 157.510 0.610 ;
        RECT 158.330 0.275 159.430 0.610 ;
        RECT 160.250 0.275 161.350 0.610 ;
        RECT 162.170 0.275 163.270 0.610 ;
        RECT 164.090 0.275 165.190 0.610 ;
        RECT 166.010 0.275 167.110 0.610 ;
        RECT 167.930 0.275 169.030 0.610 ;
        RECT 169.850 0.275 170.950 0.610 ;
        RECT 171.770 0.275 172.870 0.610 ;
        RECT 173.690 0.275 174.790 0.610 ;
        RECT 175.610 0.275 176.710 0.610 ;
        RECT 177.530 0.275 178.630 0.610 ;
        RECT 179.450 0.275 180.550 0.610 ;
        RECT 181.370 0.275 182.470 0.610 ;
        RECT 183.290 0.275 184.390 0.610 ;
        RECT 185.210 0.275 186.310 0.610 ;
        RECT 187.130 0.275 192.070 0.610 ;
        RECT 192.890 0.275 193.990 0.610 ;
        RECT 194.810 0.275 195.910 0.610 ;
        RECT 196.730 0.275 197.830 0.610 ;
        RECT 198.650 0.275 199.750 0.610 ;
        RECT 200.570 0.275 201.670 0.610 ;
        RECT 202.490 0.275 203.590 0.610 ;
        RECT 204.410 0.275 205.510 0.610 ;
        RECT 206.330 0.275 207.430 0.610 ;
        RECT 208.250 0.275 209.350 0.610 ;
        RECT 210.170 0.275 211.270 0.610 ;
        RECT 212.090 0.275 213.190 0.610 ;
        RECT 214.010 0.275 215.110 0.610 ;
        RECT 215.930 0.275 217.030 0.610 ;
        RECT 217.850 0.275 218.950 0.610 ;
        RECT 219.770 0.275 220.870 0.610 ;
        RECT 221.690 0.275 225.670 0.610 ;
        RECT 226.490 0.275 230.470 0.610 ;
        RECT 231.290 0.275 232.390 0.610 ;
        RECT 233.210 0.275 234.310 0.610 ;
        RECT 235.130 0.275 236.230 0.610 ;
        RECT 237.050 0.275 238.150 0.610 ;
        RECT 238.970 0.275 240.070 0.610 ;
        RECT 240.890 0.275 241.990 0.610 ;
        RECT 242.810 0.275 243.910 0.610 ;
        RECT 244.730 0.275 245.830 0.610 ;
        RECT 246.650 0.275 247.750 0.610 ;
        RECT 248.570 0.275 249.670 0.610 ;
        RECT 250.490 0.275 251.590 0.610 ;
        RECT 252.410 0.275 253.510 0.610 ;
        RECT 254.330 0.275 255.430 0.610 ;
        RECT 256.250 0.275 257.350 0.610 ;
        RECT 258.170 0.275 259.270 0.610 ;
        RECT 260.090 0.275 261.190 0.610 ;
        RECT 262.010 0.275 263.110 0.610 ;
        RECT 263.930 0.275 265.030 0.610 ;
        RECT 265.850 0.275 266.950 0.610 ;
        RECT 267.770 0.275 269.865 0.610 ;
      LAYER Metal3 ;
        RECT 0.335 227.630 269.905 229.845 ;
        RECT 0.610 226.810 269.630 227.630 ;
        RECT 0.335 225.950 269.905 226.810 ;
        RECT 0.610 225.130 269.630 225.950 ;
        RECT 0.335 224.270 269.905 225.130 ;
        RECT 0.610 223.450 269.630 224.270 ;
        RECT 0.335 222.590 269.905 223.450 ;
        RECT 0.610 221.770 269.630 222.590 ;
        RECT 0.335 220.910 269.905 221.770 ;
        RECT 0.610 220.090 269.630 220.910 ;
        RECT 0.335 219.230 269.905 220.090 ;
        RECT 0.610 218.410 269.630 219.230 ;
        RECT 0.335 217.550 269.905 218.410 ;
        RECT 0.610 216.730 269.630 217.550 ;
        RECT 0.335 215.870 269.905 216.730 ;
        RECT 0.610 215.050 269.630 215.870 ;
        RECT 0.335 214.190 269.905 215.050 ;
        RECT 0.610 213.370 269.630 214.190 ;
        RECT 0.335 212.510 269.905 213.370 ;
        RECT 0.610 211.690 269.630 212.510 ;
        RECT 0.335 210.830 269.905 211.690 ;
        RECT 0.610 210.010 269.630 210.830 ;
        RECT 0.335 209.150 269.905 210.010 ;
        RECT 0.610 208.330 269.630 209.150 ;
        RECT 0.335 207.470 269.905 208.330 ;
        RECT 0.610 206.650 269.630 207.470 ;
        RECT 0.335 205.790 269.905 206.650 ;
        RECT 0.610 204.970 269.630 205.790 ;
        RECT 0.335 204.110 269.905 204.970 ;
        RECT 0.610 203.290 269.630 204.110 ;
        RECT 0.335 202.430 269.905 203.290 ;
        RECT 0.610 201.610 269.630 202.430 ;
        RECT 0.335 200.750 269.905 201.610 ;
        RECT 0.610 199.930 269.630 200.750 ;
        RECT 0.335 199.070 269.905 199.930 ;
        RECT 0.610 198.250 269.630 199.070 ;
        RECT 0.335 197.390 269.905 198.250 ;
        RECT 0.610 196.570 269.630 197.390 ;
        RECT 0.335 195.710 269.905 196.570 ;
        RECT 0.610 194.890 269.630 195.710 ;
        RECT 0.335 194.030 269.905 194.890 ;
        RECT 0.610 193.210 269.630 194.030 ;
        RECT 0.335 192.350 269.905 193.210 ;
        RECT 0.610 191.530 269.630 192.350 ;
        RECT 0.335 190.670 269.905 191.530 ;
        RECT 0.790 189.850 269.630 190.670 ;
        RECT 0.335 188.990 269.905 189.850 ;
        RECT 0.610 188.170 269.630 188.990 ;
        RECT 0.335 187.310 269.905 188.170 ;
        RECT 0.610 186.490 269.630 187.310 ;
        RECT 0.335 185.630 269.905 186.490 ;
        RECT 0.610 184.810 269.630 185.630 ;
        RECT 0.335 183.950 269.905 184.810 ;
        RECT 0.610 183.130 269.630 183.950 ;
        RECT 0.335 182.270 269.905 183.130 ;
        RECT 0.610 181.450 269.630 182.270 ;
        RECT 0.335 180.590 269.905 181.450 ;
        RECT 0.610 179.770 269.630 180.590 ;
        RECT 0.335 178.910 269.905 179.770 ;
        RECT 0.610 178.090 269.630 178.910 ;
        RECT 0.335 177.230 269.905 178.090 ;
        RECT 0.610 176.410 269.630 177.230 ;
        RECT 0.335 175.550 269.905 176.410 ;
        RECT 0.610 174.730 269.630 175.550 ;
        RECT 0.335 172.190 269.905 174.730 ;
        RECT 0.610 171.370 269.630 172.190 ;
        RECT 0.335 169.670 269.905 171.370 ;
        RECT 0.610 168.850 269.630 169.670 ;
        RECT 0.335 167.990 269.905 168.850 ;
        RECT 0.610 167.170 269.630 167.990 ;
        RECT 0.335 166.310 269.905 167.170 ;
        RECT 0.610 165.490 269.630 166.310 ;
        RECT 0.335 164.630 269.905 165.490 ;
        RECT 0.610 163.810 269.630 164.630 ;
        RECT 0.335 162.950 269.905 163.810 ;
        RECT 0.610 162.130 269.630 162.950 ;
        RECT 0.335 161.270 269.905 162.130 ;
        RECT 0.610 160.450 269.630 161.270 ;
        RECT 0.335 159.590 269.905 160.450 ;
        RECT 0.610 158.770 269.630 159.590 ;
        RECT 0.335 157.910 269.905 158.770 ;
        RECT 0.610 157.090 269.630 157.910 ;
        RECT 0.335 156.230 269.905 157.090 ;
        RECT 0.610 155.410 269.630 156.230 ;
        RECT 0.335 154.550 269.905 155.410 ;
        RECT 0.610 153.730 269.630 154.550 ;
        RECT 0.335 152.870 269.905 153.730 ;
        RECT 0.610 152.050 269.630 152.870 ;
        RECT 0.335 151.190 269.905 152.050 ;
        RECT 0.610 150.370 269.630 151.190 ;
        RECT 0.335 147.830 269.905 150.370 ;
        RECT 0.610 147.010 269.630 147.830 ;
        RECT 0.335 146.150 269.905 147.010 ;
        RECT 0.610 145.330 269.630 146.150 ;
        RECT 0.335 144.470 269.905 145.330 ;
        RECT 0.610 143.650 269.630 144.470 ;
        RECT 0.335 142.790 269.905 143.650 ;
        RECT 0.610 141.970 269.630 142.790 ;
        RECT 0.335 141.110 269.905 141.970 ;
        RECT 0.610 140.290 269.630 141.110 ;
        RECT 0.335 139.430 269.905 140.290 ;
        RECT 0.610 138.610 269.630 139.430 ;
        RECT 0.335 137.750 269.905 138.610 ;
        RECT 0.610 136.930 269.630 137.750 ;
        RECT 0.335 136.070 269.905 136.930 ;
        RECT 0.610 135.250 269.630 136.070 ;
        RECT 0.335 134.390 269.905 135.250 ;
        RECT 0.610 133.570 269.630 134.390 ;
        RECT 0.335 132.710 269.905 133.570 ;
        RECT 0.610 131.890 269.630 132.710 ;
        RECT 0.335 131.030 269.905 131.890 ;
        RECT 0.610 130.210 269.630 131.030 ;
        RECT 0.335 129.350 269.905 130.210 ;
        RECT 0.610 128.530 269.630 129.350 ;
        RECT 0.335 127.670 269.905 128.530 ;
        RECT 0.610 126.850 269.630 127.670 ;
        RECT 0.335 125.990 269.905 126.850 ;
        RECT 0.610 125.170 269.630 125.990 ;
        RECT 0.335 124.310 269.905 125.170 ;
        RECT 0.610 123.490 269.630 124.310 ;
        RECT 0.335 122.630 269.905 123.490 ;
        RECT 0.610 121.810 269.630 122.630 ;
        RECT 0.335 120.110 269.905 121.810 ;
        RECT 0.610 119.290 269.630 120.110 ;
        RECT 0.335 118.430 269.905 119.290 ;
        RECT 0.610 117.610 269.630 118.430 ;
        RECT 0.335 116.750 269.905 117.610 ;
        RECT 0.610 115.930 269.630 116.750 ;
        RECT 0.335 115.070 269.905 115.930 ;
        RECT 0.610 114.250 269.630 115.070 ;
        RECT 0.335 113.390 269.905 114.250 ;
        RECT 0.610 112.570 269.630 113.390 ;
        RECT 0.335 111.710 269.905 112.570 ;
        RECT 0.610 110.890 269.630 111.710 ;
        RECT 0.335 110.030 269.905 110.890 ;
        RECT 0.610 109.210 269.630 110.030 ;
        RECT 0.335 108.350 269.905 109.210 ;
        RECT 0.610 107.530 269.630 108.350 ;
        RECT 0.335 105.830 269.905 107.530 ;
        RECT 0.610 105.010 269.630 105.830 ;
        RECT 0.335 104.150 269.905 105.010 ;
        RECT 0.610 103.330 269.630 104.150 ;
        RECT 0.335 102.470 269.905 103.330 ;
        RECT 0.610 101.650 269.630 102.470 ;
        RECT 0.335 100.790 269.905 101.650 ;
        RECT 0.610 99.970 269.630 100.790 ;
        RECT 0.335 99.110 269.905 99.970 ;
        RECT 0.610 98.290 269.630 99.110 ;
        RECT 0.335 97.430 269.905 98.290 ;
        RECT 0.610 96.610 269.630 97.430 ;
        RECT 0.335 95.750 269.905 96.610 ;
        RECT 0.610 94.930 269.630 95.750 ;
        RECT 0.335 94.070 269.905 94.930 ;
        RECT 0.610 93.250 269.630 94.070 ;
        RECT 0.335 91.550 269.905 93.250 ;
        RECT 0.610 90.730 269.630 91.550 ;
        RECT 0.335 89.870 269.905 90.730 ;
        RECT 0.610 89.050 269.630 89.870 ;
        RECT 0.335 88.190 269.905 89.050 ;
        RECT 0.610 87.370 269.630 88.190 ;
        RECT 0.335 86.510 269.905 87.370 ;
        RECT 0.610 85.690 269.630 86.510 ;
        RECT 0.335 83.990 269.905 85.690 ;
        RECT 0.610 83.170 269.630 83.990 ;
        RECT 0.335 82.310 269.905 83.170 ;
        RECT 0.610 81.490 269.630 82.310 ;
        RECT 0.335 80.630 269.905 81.490 ;
        RECT 0.610 79.810 269.630 80.630 ;
        RECT 0.335 78.950 269.905 79.810 ;
        RECT 0.610 78.130 269.630 78.950 ;
        RECT 0.335 77.270 269.905 78.130 ;
        RECT 0.610 76.450 269.630 77.270 ;
        RECT 0.335 75.590 269.905 76.450 ;
        RECT 0.610 74.770 269.630 75.590 ;
        RECT 0.335 73.910 269.905 74.770 ;
        RECT 0.610 73.090 269.630 73.910 ;
        RECT 0.335 72.230 269.905 73.090 ;
        RECT 0.610 71.410 269.630 72.230 ;
        RECT 0.335 70.550 269.905 71.410 ;
        RECT 0.610 69.730 269.630 70.550 ;
        RECT 0.335 68.870 269.905 69.730 ;
        RECT 0.610 68.050 269.630 68.870 ;
        RECT 0.335 67.190 269.905 68.050 ;
        RECT 0.610 66.370 269.630 67.190 ;
        RECT 0.335 65.510 269.905 66.370 ;
        RECT 0.610 64.690 269.630 65.510 ;
        RECT 0.335 62.150 269.905 64.690 ;
        RECT 0.610 61.330 269.630 62.150 ;
        RECT 0.335 60.470 269.905 61.330 ;
        RECT 0.610 59.650 269.630 60.470 ;
        RECT 0.335 58.790 269.905 59.650 ;
        RECT 0.610 57.970 269.630 58.790 ;
        RECT 0.335 57.110 269.905 57.970 ;
        RECT 0.610 56.290 269.630 57.110 ;
        RECT 0.335 55.430 269.905 56.290 ;
        RECT 0.610 54.610 269.630 55.430 ;
        RECT 0.335 53.750 269.905 54.610 ;
        RECT 0.610 52.930 269.630 53.750 ;
        RECT 0.335 52.070 269.905 52.930 ;
        RECT 0.610 51.250 269.630 52.070 ;
        RECT 0.335 50.390 269.905 51.250 ;
        RECT 0.610 49.570 269.630 50.390 ;
        RECT 0.335 48.710 269.905 49.570 ;
        RECT 0.610 47.890 269.630 48.710 ;
        RECT 0.335 47.030 269.905 47.890 ;
        RECT 0.610 46.210 269.630 47.030 ;
        RECT 0.335 45.350 269.905 46.210 ;
        RECT 0.610 44.530 269.630 45.350 ;
        RECT 0.335 43.670 269.905 44.530 ;
        RECT 0.610 42.850 269.630 43.670 ;
        RECT 0.335 41.990 269.905 42.850 ;
        RECT 0.610 41.170 269.630 41.990 ;
        RECT 0.335 40.310 269.905 41.170 ;
        RECT 0.610 39.490 269.630 40.310 ;
        RECT 0.335 38.630 269.905 39.490 ;
        RECT 0.610 37.810 269.630 38.630 ;
        RECT 0.335 36.950 269.905 37.810 ;
        RECT 0.610 36.130 269.630 36.950 ;
        RECT 0.335 34.430 269.905 36.130 ;
        RECT 0.610 33.610 269.630 34.430 ;
        RECT 0.335 32.750 269.905 33.610 ;
        RECT 0.610 31.930 269.630 32.750 ;
        RECT 0.335 31.070 269.905 31.930 ;
        RECT 0.610 30.250 269.630 31.070 ;
        RECT 0.335 29.390 269.905 30.250 ;
        RECT 0.610 28.570 269.630 29.390 ;
        RECT 0.335 27.710 269.905 28.570 ;
        RECT 0.610 26.890 269.630 27.710 ;
        RECT 0.335 26.030 269.905 26.890 ;
        RECT 0.610 25.210 269.630 26.030 ;
        RECT 0.335 24.350 269.905 25.210 ;
        RECT 0.610 23.530 269.630 24.350 ;
        RECT 0.335 22.670 269.905 23.530 ;
        RECT 0.610 21.850 269.630 22.670 ;
        RECT 0.335 20.990 269.905 21.850 ;
        RECT 0.610 20.170 269.630 20.990 ;
        RECT 0.335 19.310 269.905 20.170 ;
        RECT 0.610 18.490 269.630 19.310 ;
        RECT 0.335 17.630 269.905 18.490 ;
        RECT 0.610 16.810 269.630 17.630 ;
        RECT 0.335 15.950 269.905 16.810 ;
        RECT 0.610 15.130 269.630 15.950 ;
        RECT 0.335 14.270 269.905 15.130 ;
        RECT 0.610 13.450 269.630 14.270 ;
        RECT 0.335 12.590 269.905 13.450 ;
        RECT 0.610 11.770 269.630 12.590 ;
        RECT 0.335 10.910 269.905 11.770 ;
        RECT 0.610 10.090 269.630 10.910 ;
        RECT 0.335 9.230 269.905 10.090 ;
        RECT 0.610 8.410 269.630 9.230 ;
        RECT 0.335 6.710 269.905 8.410 ;
        RECT 0.610 5.890 269.630 6.710 ;
        RECT 0.335 5.030 269.905 5.890 ;
        RECT 0.610 4.210 269.630 5.030 ;
        RECT 0.335 3.350 269.905 4.210 ;
        RECT 0.610 2.530 269.630 3.350 ;
        RECT 0.335 1.670 269.905 2.530 ;
        RECT 0.610 0.850 269.630 1.670 ;
        RECT 0.335 0.315 269.905 0.850 ;
      LAYER Metal4 ;
        RECT 0.380 0.275 10.730 229.885 ;
        RECT 12.150 0.275 13.730 229.885 ;
        RECT 15.150 0.275 60.730 229.885 ;
        RECT 62.150 0.275 63.730 229.885 ;
        RECT 65.150 0.275 110.730 229.885 ;
        RECT 112.150 0.275 113.730 229.885 ;
        RECT 115.150 0.275 160.730 229.885 ;
        RECT 162.150 0.275 163.730 229.885 ;
        RECT 165.150 0.275 210.730 229.885 ;
        RECT 212.150 0.275 213.730 229.885 ;
        RECT 215.150 0.275 260.730 229.885 ;
        RECT 262.150 0.275 263.730 229.885 ;
        RECT 265.150 0.275 269.860 229.885 ;
      LAYER TopMetal1 ;
        RECT 2.060 5.380 268.180 225.900 ;
  END
END FLUT51PSDM
END LIBRARY

